VERSION 5.7 ;
  NOWIREEXTENSIONATPIN ON ;
  DIVIDERCHAR "/" ;
  BUSBITCHARS "[]" ;
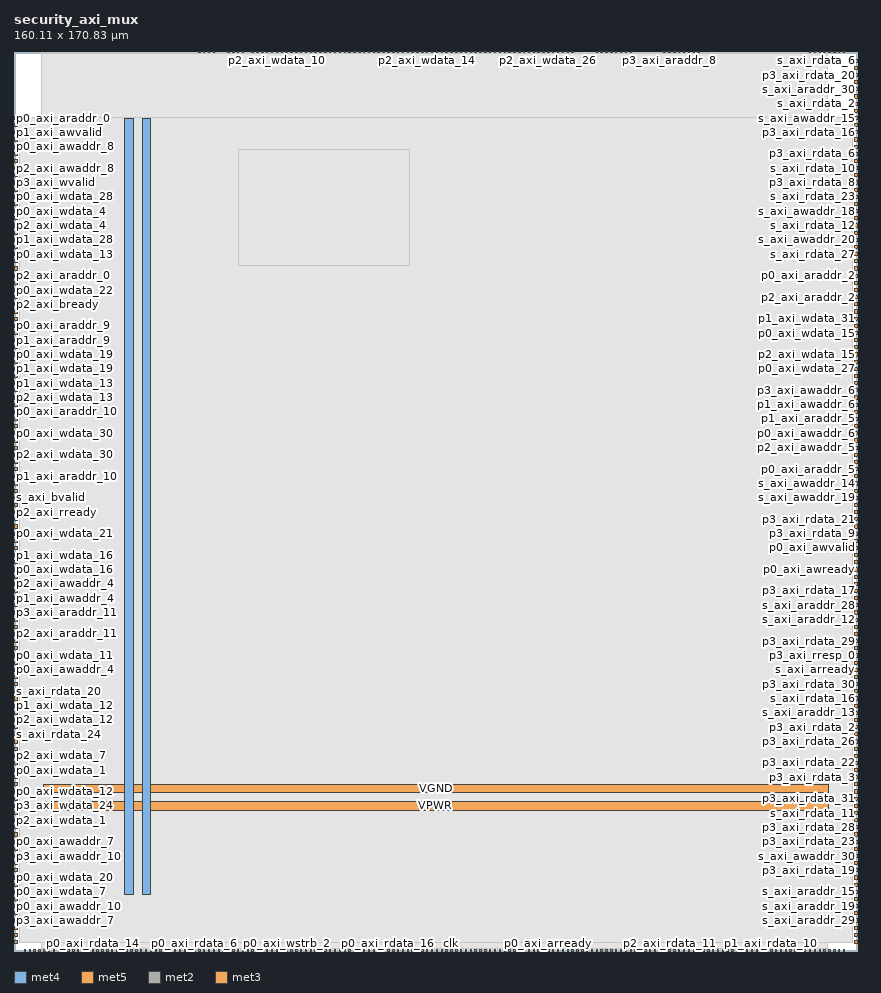
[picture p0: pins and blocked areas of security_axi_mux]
MACRO security_axi_mux
  CLASS BLOCK ;
  FOREIGN security_axi_mux ;
  ORIGIN 0.000 0.000 ;
  SIZE 160.110 BY 170.830 ;
  PIN VGND
    DIRECTION INOUT ;
    USE GROUND ;
    PORT
      LAYER met4 ;
        RECT 24.340 10.640 25.940 158.000 ;
    END
    PORT
      LAYER met5 ;
        RECT 5.520 30.030 154.560 31.630 ;
    END
  END VGND
  PIN VPWR
    DIRECTION INOUT ;
    USE POWER ;
    PORT
      LAYER met4 ;
        RECT 21.040 10.640 22.640 158.000 ;
    END
    PORT
      LAYER met5 ;
        RECT 5.520 26.730 154.560 28.330 ;
    END
  END VPWR
  PIN clk
    DIRECTION INPUT ;
    USE SIGNAL ;
    ANTENNAGATEAREA 1.286700 ;
    ANTENNADIFFAREA 0.434700 ;
    PORT
      LAYER met2 ;
        RECT 82.890 0.000 83.170 0.280 ;
    END
  END clk
  PIN p0_axi_araddr_0
    DIRECTION OUTPUT ;
    USE SIGNAL ;
    ANTENNAGATEAREA 0.434700 ;
    ANTENNADIFFAREA 1.137600 ;
    PORT
      LAYER met3 ;
        RECT 0.000 157.800 0.600 158.400 ;
    END
  END p0_axi_araddr_0
  PIN p0_axi_araddr_1
    DIRECTION OUTPUT ;
    USE SIGNAL ;
    ANTENNAGATEAREA 0.434700 ;
    ANTENNADIFFAREA 1.137600 ;
    PORT
      LAYER met2 ;
        RECT 50.690 0.000 50.970 0.280 ;
    END
  END p0_axi_araddr_1
  PIN p0_axi_araddr_10
    DIRECTION OUTPUT ;
    USE SIGNAL ;
    ANTENNAGATEAREA 0.434700 ;
    ANTENNADIFFAREA 1.137600 ;
    PORT
      LAYER met3 ;
        RECT 0.000 102.040 0.600 102.640 ;
    END
  END p0_axi_araddr_10
  PIN p0_axi_araddr_11
    DIRECTION OUTPUT ;
    USE SIGNAL ;
    ANTENNAGATEAREA 0.434700 ;
    ANTENNADIFFAREA 1.137600 ;
    PORT
      LAYER met3 ;
        RECT 0.000 1.400 0.600 2.000 ;
    END
  END p0_axi_araddr_11
  PIN p0_axi_araddr_2
    DIRECTION OUTPUT ;
    USE SIGNAL ;
    ANTENNAGATEAREA 0.434700 ;
    ANTENNADIFFAREA 1.137600 ;
    PORT
      LAYER met3 ;
        RECT 159.510 127.880 160.110 128.480 ;
    END
  END p0_axi_araddr_2
  PIN p0_axi_araddr_3
    DIRECTION OUTPUT ;
    USE SIGNAL ;
    ANTENNAGATEAREA 0.434700 ;
    ANTENNADIFFAREA 1.137600 ;
    PORT
      LAYER met2 ;
        RECT 68.170 170.550 68.450 170.830 ;
    END
  END p0_axi_araddr_3
  PIN p0_axi_araddr_4
    DIRECTION OUTPUT ;
    USE SIGNAL ;
    ANTENNAGATEAREA 0.434700 ;
    ANTENNADIFFAREA 1.137600 ;
    PORT
      LAYER met2 ;
        RECT 71.850 0.000 72.130 0.280 ;
    END
  END p0_axi_araddr_4
  PIN p0_axi_araddr_5
    DIRECTION OUTPUT ;
    USE SIGNAL ;
    ANTENNAGATEAREA 0.434700 ;
    ANTENNADIFFAREA 1.137600 ;
    PORT
      LAYER met3 ;
        RECT 159.510 91.160 160.110 91.760 ;
    END
  END p0_axi_araddr_5
  PIN p0_axi_araddr_6
    DIRECTION OUTPUT ;
    USE SIGNAL ;
    ANTENNAGATEAREA 0.434700 ;
    ANTENNADIFFAREA 1.137600 ;
    PORT
      LAYER met2 ;
        RECT 73.690 170.550 73.970 170.830 ;
    END
  END p0_axi_araddr_6
  PIN p0_axi_araddr_7
    DIRECTION OUTPUT ;
    USE SIGNAL ;
    ANTENNAGATEAREA 0.434700 ;
    ANTENNADIFFAREA 1.137600 ;
    PORT
      LAYER met2 ;
        RECT 98.530 170.550 98.810 170.830 ;
    END
  END p0_axi_araddr_7
  PIN p0_axi_araddr_8
    DIRECTION OUTPUT ;
    USE SIGNAL ;
    ANTENNAGATEAREA 0.434700 ;
    ANTENNADIFFAREA 1.137600 ;
    PORT
      LAYER met2 ;
        RECT 123.370 170.550 123.650 170.830 ;
    END
  END p0_axi_araddr_8
  PIN p0_axi_araddr_9
    DIRECTION OUTPUT ;
    USE SIGNAL ;
    ANTENNAGATEAREA 0.434700 ;
    ANTENNADIFFAREA 1.137600 ;
    PORT
      LAYER met3 ;
        RECT 0.000 118.360 0.600 118.960 ;
    END
  END p0_axi_araddr_9
  PIN p0_axi_arready
    DIRECTION INPUT ;
    USE SIGNAL ;
    ANTENNAGATEAREA 0.647700 ;
    ANTENNADIFFAREA 0.434700 ;
    PORT
      LAYER met2 ;
        RECT 101.290 0.000 101.570 0.280 ;
    END
  END p0_axi_arready
  PIN p0_axi_arvalid
    DIRECTION OUTPUT ;
    USE SIGNAL ;
    ANTENNAGATEAREA 0.434700 ;
    ANTENNADIFFAREA 1.137600 ;
    PORT
      LAYER met2 ;
        RECT 100.370 0.000 100.650 0.280 ;
    END
  END p0_axi_arvalid
  PIN p0_axi_awaddr_0
    DIRECTION OUTPUT ;
    USE SIGNAL ;
    ANTENNAGATEAREA 0.434700 ;
    ANTENNADIFFAREA 1.137600 ;
    PORT
      LAYER met2 ;
        RECT 127.050 170.550 127.330 170.830 ;
    END
  END p0_axi_awaddr_0
  PIN p0_axi_awaddr_1
    DIRECTION OUTPUT ;
    USE SIGNAL ;
    ANTENNAGATEAREA 0.434700 ;
    ANTENNADIFFAREA 1.137600 ;
    PORT
      LAYER met3 ;
        RECT 0.000 144.200 0.600 144.800 ;
    END
  END p0_axi_awaddr_1
  PIN p0_axi_awaddr_10
    DIRECTION OUTPUT ;
    USE SIGNAL ;
    ANTENNAGATEAREA 0.434700 ;
    ANTENNADIFFAREA 1.137600 ;
    PORT
      LAYER met3 ;
        RECT 0.000 8.200 0.600 8.800 ;
    END
  END p0_axi_awaddr_10
  PIN p0_axi_awaddr_11
    DIRECTION OUTPUT ;
    USE SIGNAL ;
    ANTENNAGATEAREA 0.434700 ;
    ANTENNADIFFAREA 1.137600 ;
    PORT
      LAYER met2 ;
        RECT 103.130 170.550 103.410 170.830 ;
    END
  END p0_axi_awaddr_11
  PIN p0_axi_awaddr_2
    DIRECTION OUTPUT ;
    USE SIGNAL ;
    ANTENNAGATEAREA 0.434700 ;
    ANTENNADIFFAREA 1.137600 ;
    PORT
      LAYER met2 ;
        RECT 44.250 0.000 44.530 0.280 ;
    END
  END p0_axi_awaddr_2
  PIN p0_axi_awaddr_3
    DIRECTION OUTPUT ;
    USE SIGNAL ;
    ANTENNAGATEAREA 0.434700 ;
    ANTENNADIFFAREA 1.137600 ;
    PORT
      LAYER met2 ;
        RECT 37.810 0.000 38.090 0.280 ;
    END
  END p0_axi_awaddr_3
  PIN p0_axi_awaddr_4
    DIRECTION OUTPUT ;
    USE SIGNAL ;
    ANTENNAGATEAREA 0.434700 ;
    ANTENNADIFFAREA 1.137600 ;
    PORT
      LAYER met3 ;
        RECT 0.000 53.080 0.600 53.680 ;
    END
  END p0_axi_awaddr_4
  PIN p0_axi_awaddr_5
    DIRECTION OUTPUT ;
    USE SIGNAL ;
    ANTENNAGATEAREA 0.434700 ;
    ANTENNADIFFAREA 1.137600 ;
    PORT
      LAYER met3 ;
        RECT 159.510 92.520 160.110 93.120 ;
    END
  END p0_axi_awaddr_5
  PIN p0_axi_awaddr_6
    DIRECTION OUTPUT ;
    USE SIGNAL ;
    ANTENNAGATEAREA 0.434700 ;
    ANTENNADIFFAREA 1.137600 ;
    PORT
      LAYER met3 ;
        RECT 159.510 97.960 160.110 98.560 ;
    END
  END p0_axi_awaddr_6
  PIN p0_axi_awaddr_7
    DIRECTION OUTPUT ;
    USE SIGNAL ;
    ANTENNAGATEAREA 0.434700 ;
    ANTENNADIFFAREA 1.137600 ;
    PORT
      LAYER met3 ;
        RECT 0.000 20.440 0.600 21.040 ;
    END
  END p0_axi_awaddr_7
  PIN p0_axi_awaddr_8
    DIRECTION OUTPUT ;
    USE SIGNAL ;
    ANTENNAGATEAREA 0.434700 ;
    ANTENNADIFFAREA 1.137600 ;
    PORT
      LAYER met3 ;
        RECT 0.000 152.360 0.600 152.960 ;
    END
  END p0_axi_awaddr_8
  PIN p0_axi_awaddr_9
    DIRECTION OUTPUT ;
    USE SIGNAL ;
    ANTENNAGATEAREA 0.434700 ;
    ANTENNADIFFAREA 1.137600 ;
    PORT
      LAYER met2 ;
        RECT 110.490 170.550 110.770 170.830 ;
    END
  END p0_axi_awaddr_9
  PIN p0_axi_awready
    DIRECTION INPUT ;
    USE SIGNAL ;
    ANTENNAGATEAREA 0.647700 ;
    ANTENNADIFFAREA 0.434700 ;
    PORT
      LAYER met3 ;
        RECT 159.510 72.120 160.110 72.720 ;
    END
  END p0_axi_awready
  PIN p0_axi_awvalid
    DIRECTION OUTPUT ;
    USE SIGNAL ;
    ANTENNAGATEAREA 0.434700 ;
    ANTENNADIFFAREA 1.137600 ;
    PORT
      LAYER met3 ;
        RECT 159.510 76.200 160.110 76.800 ;
    END
  END p0_axi_awvalid
  PIN p0_axi_bready
    DIRECTION OUTPUT ;
    USE SIGNAL ;
    ANTENNAGATEAREA 0.434700 ;
    ANTENNADIFFAREA 1.137600 ;
    PORT
      LAYER met3 ;
        RECT 0.000 126.520 0.600 127.120 ;
    END
  END p0_axi_bready
  PIN p0_axi_bresp_0
    DIRECTION INPUT ;
    USE SIGNAL ;
    PORT
      LAYER met2 ;
        RECT 2.850 0.000 3.130 0.280 ;
    END
  END p0_axi_bresp_0
  PIN p0_axi_bresp_1
    DIRECTION INPUT ;
    USE SIGNAL ;
    PORT
      LAYER met2 ;
        RECT 20.330 0.000 20.610 0.280 ;
    END
  END p0_axi_bresp_1
  PIN p0_axi_bvalid
    DIRECTION INPUT ;
    USE SIGNAL ;
    PORT
      LAYER met2 ;
        RECT 131.650 0.000 131.930 0.280 ;
    END
  END p0_axi_bvalid
  PIN p0_axi_rdata_0
    DIRECTION INPUT ;
    USE SIGNAL ;
    PORT
      LAYER met2 ;
        RECT 17.570 0.000 17.850 0.280 ;
    END
  END p0_axi_rdata_0
  PIN p0_axi_rdata_1
    DIRECTION INPUT ;
    USE SIGNAL ;
    PORT
      LAYER met2 ;
        RECT 152.810 0.000 153.090 0.280 ;
    END
  END p0_axi_rdata_1
  PIN p0_axi_rdata_10
    DIRECTION INPUT ;
    USE SIGNAL ;
    PORT
      LAYER met2 ;
        RECT 19.410 0.000 19.690 0.280 ;
    END
  END p0_axi_rdata_10
  PIN p0_axi_rdata_11
    DIRECTION INPUT ;
    USE SIGNAL ;
    PORT
      LAYER met2 ;
        RECT 149.130 0.000 149.410 0.280 ;
    END
  END p0_axi_rdata_11
  PIN p0_axi_rdata_12
    DIRECTION INPUT ;
    USE SIGNAL ;
    PORT
      LAYER met2 ;
        RECT 33.210 0.000 33.490 0.280 ;
    END
  END p0_axi_rdata_12
  PIN p0_axi_rdata_13
    DIRECTION INPUT ;
    USE SIGNAL ;
    PORT
      LAYER met2 ;
        RECT 27.690 0.000 27.970 0.280 ;
    END
  END p0_axi_rdata_13
  PIN p0_axi_rdata_14
    DIRECTION INPUT ;
    USE SIGNAL ;
    PORT
      LAYER met2 ;
        RECT 14.810 0.000 15.090 0.280 ;
    END
  END p0_axi_rdata_14
  PIN p0_axi_rdata_15
    DIRECTION INPUT ;
    USE SIGNAL ;
    PORT
      LAYER met2 ;
        RECT 154.650 0.000 154.930 0.280 ;
    END
  END p0_axi_rdata_15
  PIN p0_axi_rdata_16
    DIRECTION INPUT ;
    USE SIGNAL ;
    PORT
      LAYER met2 ;
        RECT 70.930 0.000 71.210 0.280 ;
    END
  END p0_axi_rdata_16
  PIN p0_axi_rdata_17
    DIRECTION INPUT ;
    USE SIGNAL ;
    PORT
      LAYER met2 ;
        RECT 30.450 0.000 30.730 0.280 ;
    END
  END p0_axi_rdata_17
  PIN p0_axi_rdata_18
    DIRECTION INPUT ;
    USE SIGNAL ;
    PORT
      LAYER met2 ;
        RECT 21.250 0.000 21.530 0.280 ;
    END
  END p0_axi_rdata_18
  PIN p0_axi_rdata_19
    DIRECTION INPUT ;
    USE SIGNAL ;
    PORT
      LAYER met2 ;
        RECT 18.490 0.000 18.770 0.280 ;
    END
  END p0_axi_rdata_19
  PIN p0_axi_rdata_2
    DIRECTION INPUT ;
    USE SIGNAL ;
    PORT
      LAYER met2 ;
        RECT 150.050 0.000 150.330 0.280 ;
    END
  END p0_axi_rdata_2
  PIN p0_axi_rdata_20
    DIRECTION INPUT ;
    USE SIGNAL ;
    PORT
      LAYER met2 ;
        RECT 146.370 0.000 146.650 0.280 ;
    END
  END p0_axi_rdata_20
  PIN p0_axi_rdata_21
    DIRECTION INPUT ;
    USE SIGNAL ;
    PORT
      LAYER met2 ;
        RECT 64.490 0.000 64.770 0.280 ;
    END
  END p0_axi_rdata_21
  PIN p0_axi_rdata_22
    DIRECTION INPUT ;
    USE SIGNAL ;
    PORT
      LAYER met2 ;
        RECT 25.850 0.000 26.130 0.280 ;
    END
  END p0_axi_rdata_22
  PIN p0_axi_rdata_23
    DIRECTION INPUT ;
    USE SIGNAL ;
    PORT
      LAYER met2 ;
        RECT 137.170 0.000 137.450 0.280 ;
    END
  END p0_axi_rdata_23
  PIN p0_axi_rdata_24
    DIRECTION INPUT ;
    USE SIGNAL ;
    PORT
      LAYER met2 ;
        RECT 32.290 0.000 32.570 0.280 ;
    END
  END p0_axi_rdata_24
  PIN p0_axi_rdata_25
    DIRECTION INPUT ;
    USE SIGNAL ;
    PORT
      LAYER met2 ;
        RECT 26.770 0.000 27.050 0.280 ;
    END
  END p0_axi_rdata_25
  PIN p0_axi_rdata_26
    DIRECTION INPUT ;
    USE SIGNAL ;
    PORT
      LAYER met2 ;
        RECT 155.570 0.000 155.850 0.280 ;
    END
  END p0_axi_rdata_26
  PIN p0_axi_rdata_27
    DIRECTION INPUT ;
    USE SIGNAL ;
    PORT
      LAYER met2 ;
        RECT 145.450 0.000 145.730 0.280 ;
    END
  END p0_axi_rdata_27
  PIN p0_axi_rdata_28
    DIRECTION INPUT ;
    USE SIGNAL ;
    PORT
      LAYER met2 ;
        RECT 69.090 0.000 69.370 0.280 ;
    END
  END p0_axi_rdata_28
  PIN p0_axi_rdata_29
    DIRECTION INPUT ;
    USE SIGNAL ;
    PORT
      LAYER met2 ;
        RECT 29.530 0.000 29.810 0.280 ;
    END
  END p0_axi_rdata_29
  PIN p0_axi_rdata_3
    DIRECTION INPUT ;
    USE SIGNAL ;
    PORT
      LAYER met2 ;
        RECT 31.370 0.000 31.650 0.280 ;
    END
  END p0_axi_rdata_3
  PIN p0_axi_rdata_30
    DIRECTION INPUT ;
    USE SIGNAL ;
    PORT
      LAYER met2 ;
        RECT 35.050 0.000 35.330 0.280 ;
    END
  END p0_axi_rdata_30
  PIN p0_axi_rdata_31
    DIRECTION INPUT ;
    USE SIGNAL ;
    PORT
      LAYER met2 ;
        RECT 47.930 0.000 48.210 0.280 ;
    END
  END p0_axi_rdata_31
  PIN p0_axi_rdata_4
    DIRECTION INPUT ;
    USE SIGNAL ;
    PORT
      LAYER met2 ;
        RECT 9.290 0.000 9.570 0.280 ;
    END
  END p0_axi_rdata_4
  PIN p0_axi_rdata_5
    DIRECTION INPUT ;
    USE SIGNAL ;
    PORT
      LAYER met2 ;
        RECT 81.050 0.000 81.330 0.280 ;
    END
  END p0_axi_rdata_5
  PIN p0_axi_rdata_6
    DIRECTION INPUT ;
    USE SIGNAL ;
    PORT
      LAYER met2 ;
        RECT 34.130 0.000 34.410 0.280 ;
    END
  END p0_axi_rdata_6
  PIN p0_axi_rdata_7
    DIRECTION INPUT ;
    USE SIGNAL ;
    PORT
      LAYER met2 ;
        RECT 87.490 0.000 87.770 0.280 ;
    END
  END p0_axi_rdata_7
  PIN p0_axi_rdata_8
    DIRECTION INPUT ;
    USE SIGNAL ;
    PORT
      LAYER met2 ;
        RECT 12.050 0.000 12.330 0.280 ;
    END
  END p0_axi_rdata_8
  PIN p0_axi_rdata_9
    DIRECTION INPUT ;
    USE SIGNAL ;
    PORT
      LAYER met2 ;
        RECT 86.570 0.000 86.850 0.280 ;
    END
  END p0_axi_rdata_9
  PIN p0_axi_rready
    DIRECTION OUTPUT ;
    USE SIGNAL ;
    ANTENNAGATEAREA 0.434700 ;
    ANTENNADIFFAREA 0.775300 ;
    PORT
      LAYER met2 ;
        RECT 66.330 0.000 66.610 0.280 ;
    END
  END p0_axi_rready
  PIN p0_axi_rresp_0
    DIRECTION INPUT ;
    USE SIGNAL ;
    PORT
      LAYER met2 ;
        RECT 16.650 0.000 16.930 0.280 ;
    END
  END p0_axi_rresp_0
  PIN p0_axi_rresp_1
    DIRECTION INPUT ;
    USE SIGNAL ;
    PORT
      LAYER met2 ;
        RECT 85.650 0.000 85.930 0.280 ;
    END
  END p0_axi_rresp_1
  PIN p0_axi_rvalid
    DIRECTION INPUT ;
    USE SIGNAL ;
    PORT
      LAYER met2 ;
        RECT 36.890 0.000 37.170 0.280 ;
    END
  END p0_axi_rvalid
  PIN p0_axi_wdata_0
    DIRECTION OUTPUT ;
    USE SIGNAL ;
    ANTENNAGATEAREA 0.434700 ;
    ANTENNADIFFAREA 1.137600 ;
    PORT
      LAYER met2 ;
        RECT 45.170 170.550 45.450 170.830 ;
    END
  END p0_axi_wdata_0
  PIN p0_axi_wdata_1
    DIRECTION OUTPUT ;
    USE SIGNAL ;
    ANTENNAGATEAREA 0.434700 ;
    ANTENNADIFFAREA 1.137600 ;
    PORT
      LAYER met3 ;
        RECT 0.000 34.040 0.600 34.640 ;
    END
  END p0_axi_wdata_1
  PIN p0_axi_wdata_10
    DIRECTION OUTPUT ;
    USE SIGNAL ;
    ANTENNAGATEAREA 0.434700 ;
    ANTENNADIFFAREA 1.137600 ;
    PORT
      LAYER met2 ;
        RECT 47.930 170.550 48.210 170.830 ;
    END
  END p0_axi_wdata_10
  PIN p0_axi_wdata_11
    DIRECTION OUTPUT ;
    USE SIGNAL ;
    ANTENNAGATEAREA 0.434700 ;
    ANTENNADIFFAREA 1.137600 ;
    PORT
      LAYER met3 ;
        RECT 0.000 55.800 0.600 56.400 ;
    END
  END p0_axi_wdata_11
  PIN p0_axi_wdata_12
    DIRECTION OUTPUT ;
    USE SIGNAL ;
    ANTENNAGATEAREA 0.434700 ;
    ANTENNADIFFAREA 1.137600 ;
    PORT
      LAYER met3 ;
        RECT 0.000 29.960 0.600 30.560 ;
    END
  END p0_axi_wdata_12
  PIN p0_axi_wdata_13
    DIRECTION OUTPUT ;
    USE SIGNAL ;
    ANTENNAGATEAREA 0.434700 ;
    ANTENNADIFFAREA 1.137600 ;
    PORT
      LAYER met3 ;
        RECT 0.000 131.960 0.600 132.560 ;
    END
  END p0_axi_wdata_13
  PIN p0_axi_wdata_14
    DIRECTION OUTPUT ;
    USE SIGNAL ;
    ANTENNAGATEAREA 0.434700 ;
    ANTENNADIFFAREA 1.137600 ;
    PORT
      LAYER met2 ;
        RECT 76.450 170.550 76.730 170.830 ;
    END
  END p0_axi_wdata_14
  PIN p0_axi_wdata_15
    DIRECTION OUTPUT ;
    USE SIGNAL ;
    ANTENNAGATEAREA 0.434700 ;
    ANTENNADIFFAREA 1.137600 ;
    PORT
      LAYER met3 ;
        RECT 159.510 117.000 160.110 117.600 ;
    END
  END p0_axi_wdata_15
  PIN p0_axi_wdata_16
    DIRECTION OUTPUT ;
    USE SIGNAL ;
    ANTENNAGATEAREA 0.434700 ;
    ANTENNADIFFAREA 1.137600 ;
    PORT
      LAYER met3 ;
        RECT 0.000 72.120 0.600 72.720 ;
    END
  END p0_axi_wdata_16
  PIN p0_axi_wdata_17
    DIRECTION OUTPUT ;
    USE SIGNAL ;
    ANTENNAGATEAREA 0.434700 ;
    ANTENNADIFFAREA 1.137600 ;
    PORT
      LAYER met2 ;
        RECT 35.050 170.550 35.330 170.830 ;
    END
  END p0_axi_wdata_17
  PIN p0_axi_wdata_18
    DIRECTION OUTPUT ;
    USE SIGNAL ;
    ANTENNAGATEAREA 0.434700 ;
    ANTENNADIFFAREA 1.137600 ;
    PORT
      LAYER met2 ;
        RECT 40.570 170.550 40.850 170.830 ;
    END
  END p0_axi_wdata_18
  PIN p0_axi_wdata_19
    DIRECTION OUTPUT ;
    USE SIGNAL ;
    ANTENNAGATEAREA 0.434700 ;
    ANTENNADIFFAREA 1.137600 ;
    PORT
      LAYER met3 ;
        RECT 0.000 112.920 0.600 113.520 ;
    END
  END p0_axi_wdata_19
  PIN p0_axi_wdata_2
    DIRECTION OUTPUT ;
    USE SIGNAL ;
    ANTENNAGATEAREA 0.434700 ;
    ANTENNADIFFAREA 1.137600 ;
    PORT
      LAYER met2 ;
        RECT 82.890 170.550 83.170 170.830 ;
    END
  END p0_axi_wdata_2
  PIN p0_axi_wdata_20
    DIRECTION OUTPUT ;
    USE SIGNAL ;
    ANTENNAGATEAREA 0.434700 ;
    ANTENNADIFFAREA 1.137600 ;
    PORT
      LAYER met3 ;
        RECT 0.000 13.640 0.600 14.240 ;
    END
  END p0_axi_wdata_20
  PIN p0_axi_wdata_21
    DIRECTION OUTPUT ;
    USE SIGNAL ;
    ANTENNAGATEAREA 0.434700 ;
    ANTENNADIFFAREA 1.137600 ;
    PORT
      LAYER met3 ;
        RECT 0.000 78.920 0.600 79.520 ;
    END
  END p0_axi_wdata_21
  PIN p0_axi_wdata_22
    DIRECTION OUTPUT ;
    USE SIGNAL ;
    ANTENNAGATEAREA 0.434700 ;
    ANTENNADIFFAREA 1.137600 ;
    PORT
      LAYER met3 ;
        RECT 0.000 125.160 0.600 125.760 ;
    END
  END p0_axi_wdata_22
  PIN p0_axi_wdata_23
    DIRECTION OUTPUT ;
    USE SIGNAL ;
    ANTENNAGATEAREA 0.434700 ;
    ANTENNADIFFAREA 1.137600 ;
    PORT
      LAYER met2 ;
        RECT 94.850 170.550 95.130 170.830 ;
    END
  END p0_axi_wdata_23
  PIN p0_axi_wdata_24
    DIRECTION OUTPUT ;
    USE SIGNAL ;
    ANTENNAGATEAREA 0.434700 ;
    ANTENNADIFFAREA 1.137600 ;
    PORT
      LAYER met2 ;
        RECT 65.410 0.000 65.690 0.280 ;
    END
  END p0_axi_wdata_24
  PIN p0_axi_wdata_25
    DIRECTION OUTPUT ;
    USE SIGNAL ;
    ANTENNAGATEAREA 0.434700 ;
    ANTENNADIFFAREA 1.137600 ;
    PORT
      LAYER met2 ;
        RECT 59.890 170.550 60.170 170.830 ;
    END
  END p0_axi_wdata_25
  PIN p0_axi_wdata_26
    DIRECTION OUTPUT ;
    USE SIGNAL ;
    ANTENNAGATEAREA 0.434700 ;
    ANTENNADIFFAREA 1.137600 ;
    PORT
      LAYER met2 ;
        RECT 99.450 170.550 99.730 170.830 ;
    END
  END p0_axi_wdata_26
  PIN p0_axi_wdata_27
    DIRECTION OUTPUT ;
    USE SIGNAL ;
    ANTENNAGATEAREA 0.434700 ;
    ANTENNADIFFAREA 1.137600 ;
    PORT
      LAYER met3 ;
        RECT 159.510 110.200 160.110 110.800 ;
    END
  END p0_axi_wdata_27
  PIN p0_axi_wdata_28
    DIRECTION OUTPUT ;
    USE SIGNAL ;
    ANTENNAGATEAREA 0.434700 ;
    ANTENNADIFFAREA 1.137600 ;
    PORT
      LAYER met3 ;
        RECT 0.000 142.840 0.600 143.440 ;
    END
  END p0_axi_wdata_28
  PIN p0_axi_wdata_29
    DIRECTION OUTPUT ;
    USE SIGNAL ;
    ANTENNAGATEAREA 0.434700 ;
    ANTENNADIFFAREA 1.137600 ;
    PORT
      LAYER met2 ;
        RECT 81.050 170.550 81.330 170.830 ;
    END
  END p0_axi_wdata_29
  PIN p0_axi_wdata_3
    DIRECTION OUTPUT ;
    USE SIGNAL ;
    ANTENNAGATEAREA 0.434700 ;
    ANTENNADIFFAREA 1.137600 ;
    PORT
      LAYER met2 ;
        RECT 60.810 170.550 61.090 170.830 ;
    END
  END p0_axi_wdata_3
  PIN p0_axi_wdata_30
    DIRECTION OUTPUT ;
    USE SIGNAL ;
    ANTENNAGATEAREA 0.434700 ;
    ANTENNADIFFAREA 1.137600 ;
    PORT
      LAYER met3 ;
        RECT 0.000 97.960 0.600 98.560 ;
    END
  END p0_axi_wdata_30
  PIN p0_axi_wdata_31
    DIRECTION OUTPUT ;
    USE SIGNAL ;
    ANTENNAGATEAREA 0.434700 ;
    ANTENNADIFFAREA 1.137600 ;
    PORT
      LAYER met3 ;
        RECT 159.510 118.360 160.110 118.960 ;
    END
  END p0_axi_wdata_31
  PIN p0_axi_wdata_4
    DIRECTION OUTPUT ;
    USE SIGNAL ;
    ANTENNAGATEAREA 0.434700 ;
    ANTENNADIFFAREA 1.137600 ;
    PORT
      LAYER met3 ;
        RECT 0.000 140.120 0.600 140.720 ;
    END
  END p0_axi_wdata_4
  PIN p0_axi_wdata_5
    DIRECTION OUTPUT ;
    USE SIGNAL ;
    ANTENNAGATEAREA 0.434700 ;
    ANTENNADIFFAREA 1.137600 ;
    PORT
      LAYER met2 ;
        RECT 39.650 0.000 39.930 0.280 ;
    END
  END p0_axi_wdata_5
  PIN p0_axi_wdata_6
    DIRECTION OUTPUT ;
    USE SIGNAL ;
    ANTENNAGATEAREA 0.434700 ;
    ANTENNADIFFAREA 1.137600 ;
    PORT
      LAYER met2 ;
        RECT 66.330 170.550 66.610 170.830 ;
    END
  END p0_axi_wdata_6
  PIN p0_axi_wdata_7
    DIRECTION OUTPUT ;
    USE SIGNAL ;
    ANTENNAGATEAREA 0.434700 ;
    ANTENNADIFFAREA 1.137600 ;
    PORT
      LAYER met3 ;
        RECT 0.000 10.920 0.600 11.520 ;
    END
  END p0_axi_wdata_7
  PIN p0_axi_wdata_8
    DIRECTION OUTPUT ;
    USE SIGNAL ;
    ANTENNAGATEAREA 0.434700 ;
    ANTENNADIFFAREA 1.137600 ;
    PORT
      LAYER met2 ;
        RECT 78.290 0.000 78.570 0.280 ;
    END
  END p0_axi_wdata_8
  PIN p0_axi_wdata_9
    DIRECTION OUTPUT ;
    USE SIGNAL ;
    ANTENNAGATEAREA 0.434700 ;
    ANTENNADIFFAREA 1.137600 ;
    PORT
      LAYER met2 ;
        RECT 47.010 170.550 47.290 170.830 ;
    END
  END p0_axi_wdata_9
  PIN p0_axi_wready
    DIRECTION INPUT ;
    USE SIGNAL ;
    PORT
      LAYER met2 ;
        RECT 7.450 0.000 7.730 0.280 ;
    END
  END p0_axi_wready
  PIN p0_axi_wstrb_0
    DIRECTION OUTPUT ;
    USE SIGNAL ;
    ANTENNAGATEAREA 0.434700 ;
    ANTENNADIFFAREA 1.137600 ;
    PORT
      LAYER met2 ;
        RECT 114.170 170.550 114.450 170.830 ;
    END
  END p0_axi_wstrb_0
  PIN p0_axi_wstrb_1
    DIRECTION OUTPUT ;
    USE SIGNAL ;
    ANTENNAGATEAREA 0.434700 ;
    ANTENNADIFFAREA 1.137600 ;
    PORT
      LAYER met3 ;
        RECT 0.000 133.320 0.600 133.920 ;
    END
  END p0_axi_wstrb_1
  PIN p0_axi_wstrb_2
    DIRECTION OUTPUT ;
    USE SIGNAL ;
    ANTENNAGATEAREA 0.434700 ;
    ANTENNADIFFAREA 1.137600 ;
    PORT
      LAYER met2 ;
        RECT 51.610 0.000 51.890 0.280 ;
    END
  END p0_axi_wstrb_2
  PIN p0_axi_wstrb_3
    DIRECTION OUTPUT ;
    USE SIGNAL ;
    ANTENNAGATEAREA 0.434700 ;
    ANTENNADIFFAREA 1.137600 ;
    PORT
      LAYER met2 ;
        RECT 88.410 170.550 88.690 170.830 ;
    END
  END p0_axi_wstrb_3
  PIN p0_axi_wvalid
    DIRECTION OUTPUT ;
    USE SIGNAL ;
    ANTENNAGATEAREA 0.434700 ;
    ANTENNADIFFAREA 0.775300 ;
    PORT
      LAYER met2 ;
        RECT 57.130 0.000 57.410 0.280 ;
    END
  END p0_axi_wvalid
  PIN p1_axi_araddr_0
    DIRECTION OUTPUT ;
    USE SIGNAL ;
    ANTENNAGATEAREA 0.434700 ;
    ANTENNADIFFAREA 1.137600 ;
    PORT
      LAYER met3 ;
        RECT 0.000 130.600 0.600 131.200 ;
    END
  END p1_axi_araddr_0
  PIN p1_axi_araddr_1
    DIRECTION OUTPUT ;
    USE SIGNAL ;
    ANTENNAGATEAREA 0.434700 ;
    ANTENNADIFFAREA 1.137600 ;
    PORT
      LAYER met2 ;
        RECT 54.370 0.000 54.650 0.280 ;
    END
  END p1_axi_araddr_1
  PIN p1_axi_araddr_10
    DIRECTION OUTPUT ;
    USE SIGNAL ;
    ANTENNAGATEAREA 0.434700 ;
    ANTENNADIFFAREA 1.137600 ;
    PORT
      LAYER met3 ;
        RECT 0.000 89.800 0.600 90.400 ;
    END
  END p1_axi_araddr_10
  PIN p1_axi_araddr_11
    DIRECTION OUTPUT ;
    USE SIGNAL ;
    ANTENNAGATEAREA 0.434700 ;
    ANTENNADIFFAREA 1.137600 ;
    PORT
      LAYER met3 ;
        RECT 0.000 61.240 0.600 61.840 ;
    END
  END p1_axi_araddr_11
  PIN p1_axi_araddr_2
    DIRECTION OUTPUT ;
    USE SIGNAL ;
    ANTENNAGATEAREA 0.434700 ;
    ANTENNADIFFAREA 1.137600 ;
    PORT
      LAYER met3 ;
        RECT 159.510 126.520 160.110 127.120 ;
    END
  END p1_axi_araddr_2
  PIN p1_axi_araddr_3
    DIRECTION OUTPUT ;
    USE SIGNAL ;
    ANTENNAGATEAREA 0.434700 ;
    ANTENNADIFFAREA 1.137600 ;
    PORT
      LAYER met2 ;
        RECT 67.250 170.550 67.530 170.830 ;
    END
  END p1_axi_araddr_3
  PIN p1_axi_araddr_4
    DIRECTION OUTPUT ;
    USE SIGNAL ;
    ANTENNAGATEAREA 0.434700 ;
    ANTENNADIFFAREA 1.137600 ;
    PORT
      LAYER met2 ;
        RECT 74.610 0.000 74.890 0.280 ;
    END
  END p1_axi_araddr_4
  PIN p1_axi_araddr_5
    DIRECTION OUTPUT ;
    USE SIGNAL ;
    ANTENNAGATEAREA 0.434700 ;
    ANTENNADIFFAREA 1.137600 ;
    PORT
      LAYER met3 ;
        RECT 159.510 100.680 160.110 101.280 ;
    END
  END p1_axi_araddr_5
  PIN p1_axi_araddr_6
    DIRECTION OUTPUT ;
    USE SIGNAL ;
    ANTENNAGATEAREA 0.434700 ;
    ANTENNADIFFAREA 1.137600 ;
    PORT
      LAYER met2 ;
        RECT 75.530 170.550 75.810 170.830 ;
    END
  END p1_axi_araddr_6
  PIN p1_axi_araddr_7
    DIRECTION OUTPUT ;
    USE SIGNAL ;
    ANTENNAGATEAREA 0.434700 ;
    ANTENNADIFFAREA 1.137600 ;
    PORT
      LAYER met2 ;
        RECT 93.010 170.550 93.290 170.830 ;
    END
  END p1_axi_araddr_7
  PIN p1_axi_araddr_8
    DIRECTION OUTPUT ;
    USE SIGNAL ;
    ANTENNAGATEAREA 0.434700 ;
    ANTENNADIFFAREA 1.137600 ;
    PORT
      LAYER met2 ;
        RECT 126.130 170.550 126.410 170.830 ;
    END
  END p1_axi_araddr_8
  PIN p1_axi_araddr_9
    DIRECTION OUTPUT ;
    USE SIGNAL ;
    ANTENNAGATEAREA 0.434700 ;
    ANTENNADIFFAREA 1.137600 ;
    PORT
      LAYER met3 ;
        RECT 0.000 115.640 0.600 116.240 ;
    END
  END p1_axi_araddr_9
  PIN p1_axi_arready
    DIRECTION INPUT ;
    USE SIGNAL ;
    PORT
      LAYER met2 ;
        RECT 13.890 0.000 14.170 0.280 ;
    END
  END p1_axi_arready
  PIN p1_axi_arvalid
    DIRECTION OUTPUT ;
    USE SIGNAL ;
    ANTENNAGATEAREA 0.434700 ;
    ANTENNADIFFAREA 0.775300 ;
    PORT
      LAYER met3 ;
        RECT 0.000 65.320 0.600 65.920 ;
    END
  END p1_axi_arvalid
  PIN p1_axi_awaddr_0
    DIRECTION OUTPUT ;
    USE SIGNAL ;
    ANTENNAGATEAREA 0.434700 ;
    ANTENNADIFFAREA 1.137600 ;
    PORT
      LAYER met2 ;
        RECT 128.890 170.550 129.170 170.830 ;
    END
  END p1_axi_awaddr_0
  PIN p1_axi_awaddr_1
    DIRECTION OUTPUT ;
    USE SIGNAL ;
    ANTENNAGATEAREA 0.434700 ;
    ANTENNADIFFAREA 1.137600 ;
    PORT
      LAYER met3 ;
        RECT 0.000 88.440 0.600 89.040 ;
    END
  END p1_axi_awaddr_1
  PIN p1_axi_awaddr_10
    DIRECTION OUTPUT ;
    USE SIGNAL ;
    ANTENNAGATEAREA 0.434700 ;
    ANTENNADIFFAREA 1.137600 ;
    PORT
      LAYER met3 ;
        RECT 0.000 19.080 0.600 19.680 ;
    END
  END p1_axi_awaddr_10
  PIN p1_axi_awaddr_11
    DIRECTION OUTPUT ;
    USE SIGNAL ;
    ANTENNAGATEAREA 0.434700 ;
    ANTENNADIFFAREA 1.137600 ;
    PORT
      LAYER met2 ;
        RECT 105.890 170.550 106.170 170.830 ;
    END
  END p1_axi_awaddr_11
  PIN p1_axi_awaddr_2
    DIRECTION OUTPUT ;
    USE SIGNAL ;
    ANTENNAGATEAREA 0.434700 ;
    ANTENNADIFFAREA 1.137600 ;
    PORT
      LAYER met2 ;
        RECT 47.010 0.000 47.290 0.280 ;
    END
  END p1_axi_awaddr_2
  PIN p1_axi_awaddr_3
    DIRECTION OUTPUT ;
    USE SIGNAL ;
    ANTENNAGATEAREA 0.434700 ;
    ANTENNADIFFAREA 1.137600 ;
    PORT
      LAYER met2 ;
        RECT 42.410 0.000 42.690 0.280 ;
    END
  END p1_axi_awaddr_3
  PIN p1_axi_awaddr_4
    DIRECTION OUTPUT ;
    USE SIGNAL ;
    ANTENNAGATEAREA 0.434700 ;
    ANTENNADIFFAREA 1.137600 ;
    PORT
      LAYER met3 ;
        RECT 0.000 66.680 0.600 67.280 ;
    END
  END p1_axi_awaddr_4
  PIN p1_axi_awaddr_5
    DIRECTION OUTPUT ;
    USE SIGNAL ;
    ANTENNAGATEAREA 0.434700 ;
    ANTENNADIFFAREA 1.137600 ;
    PORT
      LAYER met3 ;
        RECT 159.510 96.600 160.110 97.200 ;
    END
  END p1_axi_awaddr_5
  PIN p1_axi_awaddr_6
    DIRECTION OUTPUT ;
    USE SIGNAL ;
    ANTENNAGATEAREA 0.434700 ;
    ANTENNADIFFAREA 1.137600 ;
    PORT
      LAYER met3 ;
        RECT 159.510 103.400 160.110 104.000 ;
    END
  END p1_axi_awaddr_6
  PIN p1_axi_awaddr_7
    DIRECTION OUTPUT ;
    USE SIGNAL ;
    ANTENNAGATEAREA 0.434700 ;
    ANTENNADIFFAREA 1.137600 ;
    PORT
      LAYER met3 ;
        RECT 0.000 2.760 0.600 3.360 ;
    END
  END p1_axi_awaddr_7
  PIN p1_axi_awaddr_8
    DIRECTION OUTPUT ;
    USE SIGNAL ;
    ANTENNAGATEAREA 0.434700 ;
    ANTENNADIFFAREA 1.137600 ;
    PORT
      LAYER met3 ;
        RECT 0.000 151.000 0.600 151.600 ;
    END
  END p1_axi_awaddr_8
  PIN p1_axi_awaddr_9
    DIRECTION OUTPUT ;
    USE SIGNAL ;
    ANTENNAGATEAREA 0.434700 ;
    ANTENNADIFFAREA 1.137600 ;
    PORT
      LAYER met2 ;
        RECT 111.410 170.550 111.690 170.830 ;
    END
  END p1_axi_awaddr_9
  PIN p1_axi_awready
    DIRECTION INPUT ;
    USE SIGNAL ;
    PORT
      LAYER met2 ;
        RECT 12.970 0.000 13.250 0.280 ;
    END
  END p1_axi_awready
  PIN p1_axi_awvalid
    DIRECTION OUTPUT ;
    USE SIGNAL ;
    ANTENNAGATEAREA 0.434700 ;
    ANTENNADIFFAREA 0.775300 ;
    PORT
      LAYER met3 ;
        RECT 0.000 155.080 0.600 155.680 ;
    END
  END p1_axi_awvalid
  PIN p1_axi_bready
    DIRECTION OUTPUT ;
    USE SIGNAL ;
    ANTENNAGATEAREA 0.434700 ;
    ANTENNADIFFAREA 0.775300 ;
    PORT
      LAYER met3 ;
        RECT 0.000 146.920 0.600 147.520 ;
    END
  END p1_axi_bready
  PIN p1_axi_bresp_0
    DIRECTION INPUT ;
    USE SIGNAL ;
    PORT
      LAYER met2 ;
        RECT 15.730 0.000 16.010 0.280 ;
    END
  END p1_axi_bresp_0
  PIN p1_axi_bresp_1
    DIRECTION INPUT ;
    USE SIGNAL ;
    PORT
      LAYER met2 ;
        RECT 49.770 0.000 50.050 0.280 ;
    END
  END p1_axi_bresp_1
  PIN p1_axi_bvalid
    DIRECTION INPUT ;
    USE SIGNAL ;
    PORT
      LAYER met2 ;
        RECT 153.730 0.000 154.010 0.280 ;
    END
  END p1_axi_bvalid
  PIN p1_axi_rdata_0
    DIRECTION INPUT ;
    USE SIGNAL ;
    PORT
      LAYER met2 ;
        RECT 10.210 0.000 10.490 0.280 ;
    END
  END p1_axi_rdata_0
  PIN p1_axi_rdata_1
    DIRECTION INPUT ;
    USE SIGNAL ;
    PORT
      LAYER met2 ;
        RECT 24.010 0.000 24.290 0.280 ;
    END
  END p1_axi_rdata_1
  PIN p1_axi_rdata_10
    DIRECTION INPUT ;
    USE SIGNAL ;
    PORT
      LAYER met2 ;
        RECT 143.610 0.000 143.890 0.280 ;
    END
  END p1_axi_rdata_10
  PIN p1_axi_rdata_11
    DIRECTION INPUT ;
    USE SIGNAL ;
    PORT
      LAYER met2 ;
        RECT 4.690 0.000 4.970 0.280 ;
    END
  END p1_axi_rdata_11
  PIN p1_axi_rdata_12
    DIRECTION INPUT ;
    USE SIGNAL ;
    PORT
      LAYER met2 ;
        RECT 125.210 0.000 125.490 0.280 ;
    END
  END p1_axi_rdata_12
  PIN p1_axi_rdata_13
    DIRECTION INPUT ;
    USE SIGNAL ;
    PORT
      LAYER met2 ;
        RECT 11.130 0.000 11.410 0.280 ;
    END
  END p1_axi_rdata_13
  PIN p1_axi_rdata_14
    DIRECTION INPUT ;
    USE SIGNAL ;
    PORT
      LAYER met2 ;
        RECT 150.970 0.000 151.250 0.280 ;
    END
  END p1_axi_rdata_14
  PIN p1_axi_rdata_15
    DIRECTION INPUT ;
    USE SIGNAL ;
    PORT
      LAYER met2 ;
        RECT 48.850 0.000 49.130 0.280 ;
    END
  END p1_axi_rdata_15
  PIN p1_axi_rdata_16
    DIRECTION INPUT ;
    USE SIGNAL ;
    PORT
      LAYER met2 ;
        RECT 23.090 0.000 23.370 0.280 ;
    END
  END p1_axi_rdata_16
  PIN p1_axi_rdata_17
    DIRECTION INPUT ;
    USE SIGNAL ;
    PORT
      LAYER met2 ;
        RECT 1.930 0.000 2.210 0.280 ;
    END
  END p1_axi_rdata_17
  PIN p1_axi_rdata_18
    DIRECTION INPUT ;
    USE SIGNAL ;
    PORT
      LAYER met2 ;
        RECT 35.970 0.000 36.250 0.280 ;
    END
  END p1_axi_rdata_18
  PIN p1_axi_rdata_19
    DIRECTION INPUT ;
    USE SIGNAL ;
    PORT
      LAYER met2 ;
        RECT 128.890 0.000 129.170 0.280 ;
    END
  END p1_axi_rdata_19
  PIN p1_axi_rdata_2
    DIRECTION INPUT ;
    USE SIGNAL ;
    PORT
      LAYER met2 ;
        RECT 139.930 0.000 140.210 0.280 ;
    END
  END p1_axi_rdata_2
  PIN p1_axi_rdata_20
    DIRECTION INPUT ;
    USE SIGNAL ;
    PORT
      LAYER met2 ;
        RECT 8.370 0.000 8.650 0.280 ;
    END
  END p1_axi_rdata_20
  PIN p1_axi_rdata_21
    DIRECTION INPUT ;
    USE SIGNAL ;
    PORT
      LAYER met2 ;
        RECT 24.930 0.000 25.210 0.280 ;
    END
  END p1_axi_rdata_21
  PIN p1_axi_rdata_22
    DIRECTION INPUT ;
    USE SIGNAL ;
    PORT
      LAYER met2 ;
        RECT 147.290 0.000 147.570 0.280 ;
    END
  END p1_axi_rdata_22
  PIN p1_axi_rdata_23
    DIRECTION INPUT ;
    USE SIGNAL ;
    PORT
      LAYER met2 ;
        RECT 59.890 0.000 60.170 0.280 ;
    END
  END p1_axi_rdata_23
  PIN p1_axi_rdata_24
    DIRECTION INPUT ;
    USE SIGNAL ;
    PORT
      LAYER met2 ;
        RECT 140.850 0.000 141.130 0.280 ;
    END
  END p1_axi_rdata_24
  PIN p1_axi_rdata_25
    DIRECTION INPUT ;
    USE SIGNAL ;
    PORT
      LAYER met2 ;
        RECT 70.010 0.000 70.290 0.280 ;
    END
  END p1_axi_rdata_25
  PIN p1_axi_rdata_26
    DIRECTION INPUT ;
    USE SIGNAL ;
    PORT
      LAYER met2 ;
        RECT 138.090 0.000 138.370 0.280 ;
    END
  END p1_axi_rdata_26
  PIN p1_axi_rdata_27
    DIRECTION INPUT ;
    USE SIGNAL ;
    PORT
      LAYER met2 ;
        RECT 60.810 0.000 61.090 0.280 ;
    END
  END p1_axi_rdata_27
  PIN p1_axi_rdata_28
    DIRECTION INPUT ;
    USE SIGNAL ;
    PORT
      LAYER met2 ;
        RECT 61.730 0.000 62.010 0.280 ;
    END
  END p1_axi_rdata_28
  PIN p1_axi_rdata_29
    DIRECTION INPUT ;
    USE SIGNAL ;
    PORT
      LAYER met2 ;
        RECT 6.530 0.000 6.810 0.280 ;
    END
  END p1_axi_rdata_29
  PIN p1_axi_rdata_3
    DIRECTION INPUT ;
    USE SIGNAL ;
    PORT
      LAYER met2 ;
        RECT 63.570 0.000 63.850 0.280 ;
    END
  END p1_axi_rdata_3
  PIN p1_axi_rdata_30
    DIRECTION INPUT ;
    USE SIGNAL ;
    PORT
      LAYER met2 ;
        RECT 106.810 0.000 107.090 0.280 ;
    END
  END p1_axi_rdata_30
  PIN p1_axi_rdata_31
    DIRECTION INPUT ;
    USE SIGNAL ;
    PORT
      LAYER met2 ;
        RECT 108.650 0.000 108.930 0.280 ;
    END
  END p1_axi_rdata_31
  PIN p1_axi_rdata_4
    DIRECTION INPUT ;
    USE SIGNAL ;
    PORT
      LAYER met2 ;
        RECT 148.210 0.000 148.490 0.280 ;
    END
  END p1_axi_rdata_4
  PIN p1_axi_rdata_5
    DIRECTION INPUT ;
    USE SIGNAL ;
    PORT
      LAYER met2 ;
        RECT 90.250 0.000 90.530 0.280 ;
    END
  END p1_axi_rdata_5
  PIN p1_axi_rdata_6
    DIRECTION INPUT ;
    USE SIGNAL ;
    PORT
      LAYER met2 ;
        RECT 127.970 0.000 128.250 0.280 ;
    END
  END p1_axi_rdata_6
  PIN p1_axi_rdata_7
    DIRECTION INPUT ;
    USE SIGNAL ;
    PORT
      LAYER met2 ;
        RECT 109.570 0.000 109.850 0.280 ;
    END
  END p1_axi_rdata_7
  PIN p1_axi_rdata_8
    DIRECTION INPUT ;
    USE SIGNAL ;
    PORT
      LAYER met2 ;
        RECT 81.970 0.000 82.250 0.280 ;
    END
  END p1_axi_rdata_8
  PIN p1_axi_rdata_9
    DIRECTION INPUT ;
    USE SIGNAL ;
    PORT
      LAYER met2 ;
        RECT 28.610 0.000 28.890 0.280 ;
    END
  END p1_axi_rdata_9
  PIN p1_axi_rready
    DIRECTION OUTPUT ;
    USE SIGNAL ;
    ANTENNAGATEAREA 0.434700 ;
    ANTENNADIFFAREA 0.775300 ;
    PORT
      LAYER met2 ;
        RECT 58.050 0.000 58.330 0.280 ;
    END
  END p1_axi_rready
  PIN p1_axi_rresp_0
    DIRECTION INPUT ;
    USE SIGNAL ;
    PORT
      LAYER met2 ;
        RECT 97.610 0.000 97.890 0.280 ;
    END
  END p1_axi_rresp_0
  PIN p1_axi_rresp_1
    DIRECTION INPUT ;
    USE SIGNAL ;
    PORT
      LAYER met2 ;
        RECT 22.170 0.000 22.450 0.280 ;
    END
  END p1_axi_rresp_1
  PIN p1_axi_rvalid
    DIRECTION INPUT ;
    USE SIGNAL ;
    PORT
      LAYER met2 ;
        RECT 76.450 0.000 76.730 0.280 ;
    END
  END p1_axi_rvalid
  PIN p1_axi_wdata_0
    DIRECTION OUTPUT ;
    USE SIGNAL ;
    ANTENNAGATEAREA 0.434700 ;
    ANTENNADIFFAREA 1.137600 ;
    PORT
      LAYER met2 ;
        RECT 58.050 170.550 58.330 170.830 ;
    END
  END p1_axi_wdata_0
  PIN p1_axi_wdata_1
    DIRECTION OUTPUT ;
    USE SIGNAL ;
    ANTENNAGATEAREA 0.434700 ;
    ANTENNADIFFAREA 1.137600 ;
    PORT
      LAYER met3 ;
        RECT 0.000 15.000 0.600 15.600 ;
    END
  END p1_axi_wdata_1
  PIN p1_axi_wdata_10
    DIRECTION OUTPUT ;
    USE SIGNAL ;
    ANTENNAGATEAREA 0.434700 ;
    ANTENNADIFFAREA 1.137600 ;
    PORT
      LAYER met2 ;
        RECT 50.690 170.550 50.970 170.830 ;
    END
  END p1_axi_wdata_10
  PIN p1_axi_wdata_11
    DIRECTION OUTPUT ;
    USE SIGNAL ;
    ANTENNAGATEAREA 0.434700 ;
    ANTENNADIFFAREA 1.137600 ;
    PORT
      LAYER met3 ;
        RECT 0.000 51.720 0.600 52.320 ;
    END
  END p1_axi_wdata_11
  PIN p1_axi_wdata_12
    DIRECTION OUTPUT ;
    USE SIGNAL ;
    ANTENNAGATEAREA 0.434700 ;
    ANTENNADIFFAREA 1.137600 ;
    PORT
      LAYER met3 ;
        RECT 0.000 46.280 0.600 46.880 ;
    END
  END p1_axi_wdata_12
  PIN p1_axi_wdata_13
    DIRECTION OUTPUT ;
    USE SIGNAL ;
    ANTENNAGATEAREA 0.434700 ;
    ANTENNADIFFAREA 1.137600 ;
    PORT
      LAYER met3 ;
        RECT 0.000 107.480 0.600 108.080 ;
    END
  END p1_axi_wdata_13
  PIN p1_axi_wdata_14
    DIRECTION OUTPUT ;
    USE SIGNAL ;
    ANTENNAGATEAREA 0.434700 ;
    ANTENNADIFFAREA 1.137600 ;
    PORT
      LAYER met2 ;
        RECT 77.370 170.550 77.650 170.830 ;
    END
  END p1_axi_wdata_14
  PIN p1_axi_wdata_15
    DIRECTION OUTPUT ;
    USE SIGNAL ;
    ANTENNAGATEAREA 0.434700 ;
    ANTENNADIFFAREA 1.137600 ;
    PORT
      LAYER met3 ;
        RECT 159.510 115.640 160.110 116.240 ;
    END
  END p1_axi_wdata_15
  PIN p1_axi_wdata_16
    DIRECTION OUTPUT ;
    USE SIGNAL ;
    ANTENNAGATEAREA 0.434700 ;
    ANTENNADIFFAREA 1.137600 ;
    PORT
      LAYER met3 ;
        RECT 0.000 74.840 0.600 75.440 ;
    END
  END p1_axi_wdata_16
  PIN p1_axi_wdata_17
    DIRECTION OUTPUT ;
    USE SIGNAL ;
    ANTENNAGATEAREA 0.434700 ;
    ANTENNADIFFAREA 1.137600 ;
    PORT
      LAYER met2 ;
        RECT 35.970 170.550 36.250 170.830 ;
    END
  END p1_axi_wdata_17
  PIN p1_axi_wdata_18
    DIRECTION OUTPUT ;
    USE SIGNAL ;
    ANTENNAGATEAREA 0.434700 ;
    ANTENNADIFFAREA 1.137600 ;
    PORT
      LAYER met2 ;
        RECT 42.410 170.550 42.690 170.830 ;
    END
  END p1_axi_wdata_18
  PIN p1_axi_wdata_19
    DIRECTION OUTPUT ;
    USE SIGNAL ;
    ANTENNAGATEAREA 0.434700 ;
    ANTENNADIFFAREA 1.137600 ;
    PORT
      LAYER met3 ;
        RECT 0.000 110.200 0.600 110.800 ;
    END
  END p1_axi_wdata_19
  PIN p1_axi_wdata_2
    DIRECTION OUTPUT ;
    USE SIGNAL ;
    ANTENNAGATEAREA 0.434700 ;
    ANTENNADIFFAREA 1.137600 ;
    PORT
      LAYER met2 ;
        RECT 85.650 170.550 85.930 170.830 ;
    END
  END p1_axi_wdata_2
  PIN p1_axi_wdata_20
    DIRECTION OUTPUT ;
    USE SIGNAL ;
    ANTENNAGATEAREA 0.434700 ;
    ANTENNADIFFAREA 1.137600 ;
    PORT
      LAYER met3 ;
        RECT 0.000 47.640 0.600 48.240 ;
    END
  END p1_axi_wdata_20
  PIN p1_axi_wdata_21
    DIRECTION OUTPUT ;
    USE SIGNAL ;
    ANTENNAGATEAREA 0.434700 ;
    ANTENNADIFFAREA 1.137600 ;
    PORT
      LAYER met3 ;
        RECT 0.000 156.440 0.600 157.040 ;
    END
  END p1_axi_wdata_21
  PIN p1_axi_wdata_22
    DIRECTION OUTPUT ;
    USE SIGNAL ;
    ANTENNAGATEAREA 0.434700 ;
    ANTENNADIFFAREA 1.137600 ;
    PORT
      LAYER met3 ;
        RECT 0.000 123.800 0.600 124.400 ;
    END
  END p1_axi_wdata_22
  PIN p1_axi_wdata_23
    DIRECTION OUTPUT ;
    USE SIGNAL ;
    ANTENNAGATEAREA 0.434700 ;
    ANTENNADIFFAREA 1.137600 ;
    PORT
      LAYER met2 ;
        RECT 97.610 170.550 97.890 170.830 ;
    END
  END p1_axi_wdata_23
  PIN p1_axi_wdata_24
    DIRECTION OUTPUT ;
    USE SIGNAL ;
    ANTENNAGATEAREA 0.434700 ;
    ANTENNADIFFAREA 1.137600 ;
    PORT
      LAYER met2 ;
        RECT 68.170 0.000 68.450 0.280 ;
    END
  END p1_axi_wdata_24
  PIN p1_axi_wdata_25
    DIRECTION OUTPUT ;
    USE SIGNAL ;
    ANTENNAGATEAREA 0.434700 ;
    ANTENNADIFFAREA 1.137600 ;
    PORT
      LAYER met2 ;
        RECT 56.210 170.550 56.490 170.830 ;
    END
  END p1_axi_wdata_25
  PIN p1_axi_wdata_26
    DIRECTION OUTPUT ;
    USE SIGNAL ;
    ANTENNAGATEAREA 0.434700 ;
    ANTENNADIFFAREA 1.137600 ;
    PORT
      LAYER met2 ;
        RECT 102.210 170.550 102.490 170.830 ;
    END
  END p1_axi_wdata_26
  PIN p1_axi_wdata_27
    DIRECTION OUTPUT ;
    USE SIGNAL ;
    ANTENNAGATEAREA 0.434700 ;
    ANTENNADIFFAREA 1.137600 ;
    PORT
      LAYER met3 ;
        RECT 159.510 111.560 160.110 112.160 ;
    END
  END p1_axi_wdata_27
  PIN p1_axi_wdata_28
    DIRECTION OUTPUT ;
    USE SIGNAL ;
    ANTENNAGATEAREA 0.434700 ;
    ANTENNADIFFAREA 1.137600 ;
    PORT
      LAYER met3 ;
        RECT 0.000 134.680 0.600 135.280 ;
    END
  END p1_axi_wdata_28
  PIN p1_axi_wdata_29
    DIRECTION OUTPUT ;
    USE SIGNAL ;
    ANTENNAGATEAREA 0.434700 ;
    ANTENNADIFFAREA 1.137600 ;
    PORT
      LAYER met2 ;
        RECT 81.970 170.550 82.250 170.830 ;
    END
  END p1_axi_wdata_29
  PIN p1_axi_wdata_3
    DIRECTION OUTPUT ;
    USE SIGNAL ;
    ANTENNAGATEAREA 0.434700 ;
    ANTENNADIFFAREA 1.137600 ;
    PORT
      LAYER met2 ;
        RECT 61.730 170.550 62.010 170.830 ;
    END
  END p1_axi_wdata_3
  PIN p1_axi_wdata_30
    DIRECTION OUTPUT ;
    USE SIGNAL ;
    ANTENNAGATEAREA 0.434700 ;
    ANTENNADIFFAREA 1.137600 ;
    PORT
      LAYER met3 ;
        RECT 0.000 96.600 0.600 97.200 ;
    END
  END p1_axi_wdata_30
  PIN p1_axi_wdata_31
    DIRECTION OUTPUT ;
    USE SIGNAL ;
    ANTENNAGATEAREA 0.434700 ;
    ANTENNADIFFAREA 1.137600 ;
    PORT
      LAYER met3 ;
        RECT 159.510 119.720 160.110 120.320 ;
    END
  END p1_axi_wdata_31
  PIN p1_axi_wdata_4
    DIRECTION OUTPUT ;
    USE SIGNAL ;
    ANTENNAGATEAREA 0.434700 ;
    ANTENNADIFFAREA 1.137600 ;
    PORT
      LAYER met3 ;
        RECT 0.000 138.760 0.600 139.360 ;
    END
  END p1_axi_wdata_4
  PIN p1_axi_wdata_5
    DIRECTION OUTPUT ;
    USE SIGNAL ;
    ANTENNAGATEAREA 0.434700 ;
    ANTENNADIFFAREA 1.137600 ;
    PORT
      LAYER met2 ;
        RECT 40.570 0.000 40.850 0.280 ;
    END
  END p1_axi_wdata_5
  PIN p1_axi_wdata_6
    DIRECTION OUTPUT ;
    USE SIGNAL ;
    ANTENNAGATEAREA 0.434700 ;
    ANTENNADIFFAREA 1.137600 ;
    PORT
      LAYER met2 ;
        RECT 71.850 170.550 72.130 170.830 ;
    END
  END p1_axi_wdata_6
  PIN p1_axi_wdata_7
    DIRECTION OUTPUT ;
    USE SIGNAL ;
    ANTENNAGATEAREA 0.434700 ;
    ANTENNADIFFAREA 1.137600 ;
    PORT
      LAYER met3 ;
        RECT 0.000 54.440 0.600 55.040 ;
    END
  END p1_axi_wdata_7
  PIN p1_axi_wdata_8
    DIRECTION OUTPUT ;
    USE SIGNAL ;
    ANTENNAGATEAREA 0.434700 ;
    ANTENNADIFFAREA 1.137600 ;
    PORT
      LAYER met2 ;
        RECT 80.130 0.000 80.410 0.280 ;
    END
  END p1_axi_wdata_8
  PIN p1_axi_wdata_9
    DIRECTION OUTPUT ;
    USE SIGNAL ;
    ANTENNAGATEAREA 0.434700 ;
    ANTENNADIFFAREA 1.137600 ;
    PORT
      LAYER met2 ;
        RECT 54.370 170.550 54.650 170.830 ;
    END
  END p1_axi_wdata_9
  PIN p1_axi_wready
    DIRECTION INPUT ;
    USE SIGNAL ;
    PORT
      LAYER met2 ;
        RECT 98.530 0.000 98.810 0.280 ;
    END
  END p1_axi_wready
  PIN p1_axi_wstrb_0
    DIRECTION OUTPUT ;
    USE SIGNAL ;
    ANTENNAGATEAREA 0.434700 ;
    ANTENNADIFFAREA 1.137600 ;
    PORT
      LAYER met2 ;
        RECT 115.090 170.550 115.370 170.830 ;
    END
  END p1_axi_wstrb_0
  PIN p1_axi_wstrb_1
    DIRECTION OUTPUT ;
    USE SIGNAL ;
    ANTENNAGATEAREA 0.434700 ;
    ANTENNADIFFAREA 1.137600 ;
    PORT
      LAYER met2 ;
        RECT 63.570 170.550 63.850 170.830 ;
    END
  END p1_axi_wstrb_1
  PIN p1_axi_wstrb_2
    DIRECTION OUTPUT ;
    USE SIGNAL ;
    ANTENNAGATEAREA 0.434700 ;
    ANTENNADIFFAREA 1.137600 ;
    PORT
      LAYER met2 ;
        RECT 55.290 0.000 55.570 0.280 ;
    END
  END p1_axi_wstrb_2
  PIN p1_axi_wstrb_3
    DIRECTION OUTPUT ;
    USE SIGNAL ;
    ANTENNAGATEAREA 0.434700 ;
    ANTENNADIFFAREA 1.137600 ;
    PORT
      LAYER met2 ;
        RECT 89.330 170.550 89.610 170.830 ;
    END
  END p1_axi_wstrb_3
  PIN p1_axi_wvalid
    DIRECTION OUTPUT ;
    USE SIGNAL ;
    ANTENNAGATEAREA 0.434700 ;
    ANTENNADIFFAREA 0.775300 ;
    PORT
      LAYER met2 ;
        RECT 62.650 0.000 62.930 0.280 ;
    END
  END p1_axi_wvalid
  PIN p2_axi_araddr_0
    DIRECTION OUTPUT ;
    USE SIGNAL ;
    ANTENNAGATEAREA 0.434700 ;
    ANTENNADIFFAREA 1.137600 ;
    PORT
      LAYER met3 ;
        RECT 0.000 127.880 0.600 128.480 ;
    END
  END p2_axi_araddr_0
  PIN p2_axi_araddr_1
    DIRECTION OUTPUT ;
    USE SIGNAL ;
    ANTENNAGATEAREA 0.434700 ;
    ANTENNADIFFAREA 1.137600 ;
    PORT
      LAYER met2 ;
        RECT 52.530 0.000 52.810 0.280 ;
    END
  END p2_axi_araddr_1
  PIN p2_axi_araddr_10
    DIRECTION OUTPUT ;
    USE SIGNAL ;
    ANTENNAGATEAREA 0.434700 ;
    ANTENNADIFFAREA 1.137600 ;
    PORT
      LAYER met3 ;
        RECT 0.000 91.160 0.600 91.760 ;
    END
  END p2_axi_araddr_10
  PIN p2_axi_araddr_11
    DIRECTION OUTPUT ;
    USE SIGNAL ;
    ANTENNAGATEAREA 0.434700 ;
    ANTENNADIFFAREA 1.137600 ;
    PORT
      LAYER met3 ;
        RECT 0.000 59.880 0.600 60.480 ;
    END
  END p2_axi_araddr_11
  PIN p2_axi_araddr_2
    DIRECTION OUTPUT ;
    USE SIGNAL ;
    ANTENNAGATEAREA 0.434700 ;
    ANTENNADIFFAREA 1.137600 ;
    PORT
      LAYER met3 ;
        RECT 159.510 123.800 160.110 124.400 ;
    END
  END p2_axi_araddr_2
  PIN p2_axi_araddr_3
    DIRECTION OUTPUT ;
    USE SIGNAL ;
    ANTENNAGATEAREA 0.434700 ;
    ANTENNADIFFAREA 1.137600 ;
    PORT
      LAYER met2 ;
        RECT 69.090 170.550 69.370 170.830 ;
    END
  END p2_axi_araddr_3
  PIN p2_axi_araddr_4
    DIRECTION OUTPUT ;
    USE SIGNAL ;
    ANTENNAGATEAREA 0.434700 ;
    ANTENNADIFFAREA 1.137600 ;
    PORT
      LAYER met2 ;
        RECT 73.690 0.000 73.970 0.280 ;
    END
  END p2_axi_araddr_4
  PIN p2_axi_araddr_5
    DIRECTION OUTPUT ;
    USE SIGNAL ;
    ANTENNAGATEAREA 0.434700 ;
    ANTENNADIFFAREA 1.137600 ;
    PORT
      LAYER met3 ;
        RECT 159.510 102.040 160.110 102.640 ;
    END
  END p2_axi_araddr_5
  PIN p2_axi_araddr_6
    DIRECTION OUTPUT ;
    USE SIGNAL ;
    ANTENNAGATEAREA 0.434700 ;
    ANTENNADIFFAREA 1.137600 ;
    PORT
      LAYER met2 ;
        RECT 80.130 170.550 80.410 170.830 ;
    END
  END p2_axi_araddr_6
  PIN p2_axi_araddr_7
    DIRECTION OUTPUT ;
    USE SIGNAL ;
    ANTENNAGATEAREA 0.434700 ;
    ANTENNADIFFAREA 1.137600 ;
    PORT
      LAYER met2 ;
        RECT 91.170 170.550 91.450 170.830 ;
    END
  END p2_axi_araddr_7
  PIN p2_axi_araddr_8
    DIRECTION OUTPUT ;
    USE SIGNAL ;
    ANTENNAGATEAREA 0.434700 ;
    ANTENNADIFFAREA 1.137600 ;
    PORT
      LAYER met2 ;
        RECT 125.210 170.550 125.490 170.830 ;
    END
  END p2_axi_araddr_8
  PIN p2_axi_araddr_9
    DIRECTION OUTPUT ;
    USE SIGNAL ;
    ANTENNAGATEAREA 0.434700 ;
    ANTENNADIFFAREA 1.137600 ;
    PORT
      LAYER met3 ;
        RECT 0.000 117.000 0.600 117.600 ;
    END
  END p2_axi_araddr_9
  PIN p2_axi_arready
    DIRECTION INPUT ;
    USE SIGNAL ;
    PORT
      LAYER met2 ;
        RECT 75.530 0.000 75.810 0.280 ;
    END
  END p2_axi_arready
  PIN p2_axi_arvalid
    DIRECTION OUTPUT ;
    USE SIGNAL ;
    ANTENNAGATEAREA 0.434700 ;
    ANTENNADIFFAREA 1.137600 ;
    PORT
      LAYER met2 ;
        RECT 103.130 0.000 103.410 0.280 ;
    END
  END p2_axi_arvalid
  PIN p2_axi_awaddr_0
    DIRECTION OUTPUT ;
    USE SIGNAL ;
    ANTENNAGATEAREA 0.434700 ;
    ANTENNADIFFAREA 1.137600 ;
    PORT
      LAYER met2 ;
        RECT 129.810 170.550 130.090 170.830 ;
    END
  END p2_axi_awaddr_0
  PIN p2_axi_awaddr_1
    DIRECTION OUTPUT ;
    USE SIGNAL ;
    ANTENNAGATEAREA 0.434700 ;
    ANTENNADIFFAREA 1.137600 ;
    PORT
      LAYER met3 ;
        RECT 0.000 99.320 0.600 99.920 ;
    END
  END p2_axi_awaddr_1
  PIN p2_axi_awaddr_10
    DIRECTION OUTPUT ;
    USE SIGNAL ;
    ANTENNAGATEAREA 0.434700 ;
    ANTENNADIFFAREA 1.137600 ;
    PORT
      LAYER met3 ;
        RECT 0.000 6.840 0.600 7.440 ;
    END
  END p2_axi_awaddr_10
  PIN p2_axi_awaddr_11
    DIRECTION OUTPUT ;
    USE SIGNAL ;
    ANTENNAGATEAREA 0.434700 ;
    ANTENNADIFFAREA 1.137600 ;
    PORT
      LAYER met2 ;
        RECT 104.970 170.550 105.250 170.830 ;
    END
  END p2_axi_awaddr_11
  PIN p2_axi_awaddr_2
    DIRECTION OUTPUT ;
    USE SIGNAL ;
    ANTENNAGATEAREA 0.434700 ;
    ANTENNADIFFAREA 1.137600 ;
    PORT
      LAYER met2 ;
        RECT 46.090 0.000 46.370 0.280 ;
    END
  END p2_axi_awaddr_2
  PIN p2_axi_awaddr_3
    DIRECTION OUTPUT ;
    USE SIGNAL ;
    ANTENNAGATEAREA 0.434700 ;
    ANTENNADIFFAREA 1.137600 ;
    PORT
      LAYER met2 ;
        RECT 43.330 0.000 43.610 0.280 ;
    END
  END p2_axi_awaddr_3
  PIN p2_axi_awaddr_4
    DIRECTION OUTPUT ;
    USE SIGNAL ;
    ANTENNAGATEAREA 0.434700 ;
    ANTENNADIFFAREA 1.137600 ;
    PORT
      LAYER met3 ;
        RECT 0.000 69.400 0.600 70.000 ;
    END
  END p2_axi_awaddr_4
  PIN p2_axi_awaddr_5
    DIRECTION OUTPUT ;
    USE SIGNAL ;
    ANTENNAGATEAREA 0.434700 ;
    ANTENNADIFFAREA 1.137600 ;
    PORT
      LAYER met3 ;
        RECT 159.510 95.240 160.110 95.840 ;
    END
  END p2_axi_awaddr_5
  PIN p2_axi_awaddr_6
    DIRECTION OUTPUT ;
    USE SIGNAL ;
    ANTENNAGATEAREA 0.434700 ;
    ANTENNADIFFAREA 1.137600 ;
    PORT
      LAYER met3 ;
        RECT 159.510 104.760 160.110 105.360 ;
    END
  END p2_axi_awaddr_6
  PIN p2_axi_awaddr_7
    DIRECTION OUTPUT ;
    USE SIGNAL ;
    ANTENNAGATEAREA 0.434700 ;
    ANTENNADIFFAREA 1.137600 ;
    PORT
      LAYER met3 ;
        RECT 0.000 9.560 0.600 10.160 ;
    END
  END p2_axi_awaddr_7
  PIN p2_axi_awaddr_8
    DIRECTION OUTPUT ;
    USE SIGNAL ;
    ANTENNAGATEAREA 0.434700 ;
    ANTENNADIFFAREA 1.137600 ;
    PORT
      LAYER met3 ;
        RECT 0.000 148.280 0.600 148.880 ;
    END
  END p2_axi_awaddr_8
  PIN p2_axi_awaddr_9
    DIRECTION OUTPUT ;
    USE SIGNAL ;
    ANTENNAGATEAREA 0.434700 ;
    ANTENNADIFFAREA 1.137600 ;
    PORT
      LAYER met2 ;
        RECT 112.330 170.550 112.610 170.830 ;
    END
  END p2_axi_awaddr_9
  PIN p2_axi_awready
    DIRECTION INPUT ;
    USE SIGNAL ;
    PORT
      LAYER met2 ;
        RECT 129.810 0.000 130.090 0.280 ;
    END
  END p2_axi_awready
  PIN p2_axi_awvalid
    DIRECTION OUTPUT ;
    USE SIGNAL ;
    ANTENNAGATEAREA 0.434700 ;
    ANTENNADIFFAREA 1.137600 ;
    PORT
      LAYER met3 ;
        RECT 159.510 74.840 160.110 75.440 ;
    END
  END p2_axi_awvalid
  PIN p2_axi_bready
    DIRECTION OUTPUT ;
    USE SIGNAL ;
    ANTENNAGATEAREA 0.434700 ;
    ANTENNADIFFAREA 1.137600 ;
    PORT
      LAYER met3 ;
        RECT 0.000 122.440 0.600 123.040 ;
    END
  END p2_axi_bready
  PIN p2_axi_bresp_0
    DIRECTION INPUT ;
    USE SIGNAL ;
    PORT
      LAYER met2 ;
        RECT 77.370 0.000 77.650 0.280 ;
    END
  END p2_axi_bresp_0
  PIN p2_axi_bresp_1
    DIRECTION INPUT ;
    USE SIGNAL ;
    PORT
      LAYER met2 ;
        RECT 99.450 0.000 99.730 0.280 ;
    END
  END p2_axi_bresp_1
  PIN p2_axi_bvalid
    DIRECTION INPUT ;
    USE SIGNAL ;
    PORT
      LAYER met2 ;
        RECT 93.930 0.000 94.210 0.280 ;
    END
  END p2_axi_bvalid
  PIN p2_axi_rdata_0
    DIRECTION INPUT ;
    USE SIGNAL ;
    PORT
      LAYER met2 ;
        RECT 83.810 0.000 84.090 0.280 ;
    END
  END p2_axi_rdata_0
  PIN p2_axi_rdata_1
    DIRECTION INPUT ;
    USE SIGNAL ;
    PORT
      LAYER met2 ;
        RECT 134.410 0.000 134.690 0.280 ;
    END
  END p2_axi_rdata_1
  PIN p2_axi_rdata_10
    DIRECTION INPUT ;
    USE SIGNAL ;
    PORT
      LAYER met2 ;
        RECT 130.730 0.000 131.010 0.280 ;
    END
  END p2_axi_rdata_10
  PIN p2_axi_rdata_11
    DIRECTION INPUT ;
    USE SIGNAL ;
    PORT
      LAYER met2 ;
        RECT 124.290 0.000 124.570 0.280 ;
    END
  END p2_axi_rdata_11
  PIN p2_axi_rdata_12
    DIRECTION INPUT ;
    USE SIGNAL ;
    PORT
      LAYER met2 ;
        RECT 135.330 0.000 135.610 0.280 ;
    END
  END p2_axi_rdata_12
  PIN p2_axi_rdata_13
    DIRECTION INPUT ;
    USE SIGNAL ;
    PORT
      LAYER met2 ;
        RECT 84.730 0.000 85.010 0.280 ;
    END
  END p2_axi_rdata_13
  PIN p2_axi_rdata_14
    DIRECTION INPUT ;
    USE SIGNAL ;
    PORT
      LAYER met2 ;
        RECT 89.330 0.000 89.610 0.280 ;
    END
  END p2_axi_rdata_14
  PIN p2_axi_rdata_15
    DIRECTION INPUT ;
    USE SIGNAL ;
    PORT
      LAYER met2 ;
        RECT 96.690 0.000 96.970 0.280 ;
    END
  END p2_axi_rdata_15
  PIN p2_axi_rdata_16
    DIRECTION INPUT ;
    USE SIGNAL ;
    PORT
      LAYER met2 ;
        RECT 91.170 0.000 91.450 0.280 ;
    END
  END p2_axi_rdata_16
  PIN p2_axi_rdata_17
    DIRECTION INPUT ;
    USE SIGNAL ;
    PORT
      LAYER met2 ;
        RECT 88.410 0.000 88.690 0.280 ;
    END
  END p2_axi_rdata_17
  PIN p2_axi_rdata_18
    DIRECTION INPUT ;
    USE SIGNAL ;
    PORT
      LAYER met2 ;
        RECT 93.010 0.000 93.290 0.280 ;
    END
  END p2_axi_rdata_18
  PIN p2_axi_rdata_19
    DIRECTION INPUT ;
    USE SIGNAL ;
    PORT
      LAYER met2 ;
        RECT 5.610 0.000 5.890 0.280 ;
    END
  END p2_axi_rdata_19
  PIN p2_axi_rdata_2
    DIRECTION INPUT ;
    USE SIGNAL ;
    PORT
      LAYER met2 ;
        RECT 94.850 0.000 95.130 0.280 ;
    END
  END p2_axi_rdata_2
  PIN p2_axi_rdata_20
    DIRECTION INPUT ;
    USE SIGNAL ;
    PORT
      LAYER met2 ;
        RECT 92.090 0.000 92.370 0.280 ;
    END
  END p2_axi_rdata_20
  PIN p2_axi_rdata_21
    DIRECTION INPUT ;
    USE SIGNAL ;
    PORT
      LAYER met2 ;
        RECT 105.890 0.000 106.170 0.280 ;
    END
  END p2_axi_rdata_21
  PIN p2_axi_rdata_22
    DIRECTION INPUT ;
    USE SIGNAL ;
    PORT
      LAYER met2 ;
        RECT 116.010 0.000 116.290 0.280 ;
    END
  END p2_axi_rdata_22
  PIN p2_axi_rdata_23
    DIRECTION INPUT ;
    USE SIGNAL ;
    PORT
      LAYER met2 ;
        RECT 115.090 0.000 115.370 0.280 ;
    END
  END p2_axi_rdata_23
  PIN p2_axi_rdata_24
    DIRECTION INPUT ;
    USE SIGNAL ;
    PORT
      LAYER met2 ;
        RECT 95.770 0.000 96.050 0.280 ;
    END
  END p2_axi_rdata_24
  PIN p2_axi_rdata_25
    DIRECTION INPUT ;
    USE SIGNAL ;
    PORT
      LAYER met2 ;
        RECT 142.690 0.000 142.970 0.280 ;
    END
  END p2_axi_rdata_25
  PIN p2_axi_rdata_26
    DIRECTION INPUT ;
    USE SIGNAL ;
    PORT
      LAYER met2 ;
        RECT 3.770 0.000 4.050 0.280 ;
    END
  END p2_axi_rdata_26
  PIN p2_axi_rdata_27
    DIRECTION INPUT ;
    USE SIGNAL ;
    PORT
      LAYER met2 ;
        RECT 102.210 0.000 102.490 0.280 ;
    END
  END p2_axi_rdata_27
  PIN p2_axi_rdata_28
    DIRECTION INPUT ;
    USE SIGNAL ;
    PORT
      LAYER met2 ;
        RECT 117.850 0.000 118.130 0.280 ;
    END
  END p2_axi_rdata_28
  PIN p2_axi_rdata_29
    DIRECTION INPUT ;
    USE SIGNAL ;
    PORT
      LAYER met2 ;
        RECT 104.050 0.000 104.330 0.280 ;
    END
  END p2_axi_rdata_29
  PIN p2_axi_rdata_3
    DIRECTION INPUT ;
    USE SIGNAL ;
    PORT
      LAYER met2 ;
        RECT 104.970 0.000 105.250 0.280 ;
    END
  END p2_axi_rdata_3
  PIN p2_axi_rdata_30
    DIRECTION INPUT ;
    USE SIGNAL ;
    PORT
      LAYER met2 ;
        RECT 122.450 0.000 122.730 0.280 ;
    END
  END p2_axi_rdata_30
  PIN p2_axi_rdata_31
    DIRECTION INPUT ;
    USE SIGNAL ;
    PORT
      LAYER met2 ;
        RECT 113.250 0.000 113.530 0.280 ;
    END
  END p2_axi_rdata_31
  PIN p2_axi_rdata_4
    DIRECTION INPUT ;
    USE SIGNAL ;
    PORT
      LAYER met2 ;
        RECT 107.730 0.000 108.010 0.280 ;
    END
  END p2_axi_rdata_4
  PIN p2_axi_rdata_5
    DIRECTION INPUT ;
    USE SIGNAL ;
    PORT
      LAYER met2 ;
        RECT 141.770 0.000 142.050 0.280 ;
    END
  END p2_axi_rdata_5
  PIN p2_axi_rdata_6
    DIRECTION INPUT ;
    USE SIGNAL ;
    PORT
      LAYER met2 ;
        RECT 151.890 0.000 152.170 0.280 ;
    END
  END p2_axi_rdata_6
  PIN p2_axi_rdata_7
    DIRECTION INPUT ;
    USE SIGNAL ;
    PORT
      LAYER met2 ;
        RECT 144.530 0.000 144.810 0.280 ;
    END
  END p2_axi_rdata_7
  PIN p2_axi_rdata_8
    DIRECTION INPUT ;
    USE SIGNAL ;
    PORT
      LAYER met2 ;
        RECT 111.410 0.000 111.690 0.280 ;
    END
  END p2_axi_rdata_8
  PIN p2_axi_rdata_9
    DIRECTION INPUT ;
    USE SIGNAL ;
    PORT
      LAYER met2 ;
        RECT 112.330 0.000 112.610 0.280 ;
    END
  END p2_axi_rdata_9
  PIN p2_axi_rready
    DIRECTION OUTPUT ;
    USE SIGNAL ;
    ANTENNAGATEAREA 0.434700 ;
    ANTENNADIFFAREA 0.775300 ;
    PORT
      LAYER met3 ;
        RECT 0.000 83.000 0.600 83.600 ;
    END
  END p2_axi_rready
  PIN p2_axi_rresp_0
    DIRECTION INPUT ;
    USE SIGNAL ;
    PORT
      LAYER met2 ;
        RECT 119.690 0.000 119.970 0.280 ;
    END
  END p2_axi_rresp_0
  PIN p2_axi_rresp_1
    DIRECTION INPUT ;
    USE SIGNAL ;
    PORT
      LAYER met2 ;
        RECT 110.490 0.000 110.770 0.280 ;
    END
  END p2_axi_rresp_1
  PIN p2_axi_rvalid
    DIRECTION INPUT ;
    USE SIGNAL ;
    PORT
      LAYER met2 ;
        RECT 157.410 0.000 157.690 0.280 ;
    END
  END p2_axi_rvalid
  PIN p2_axi_wdata_0
    DIRECTION OUTPUT ;
    USE SIGNAL ;
    ANTENNAGATEAREA 0.434700 ;
    ANTENNADIFFAREA 1.137600 ;
    PORT
      LAYER met2 ;
        RECT 58.970 170.550 59.250 170.830 ;
    END
  END p2_axi_wdata_0
  PIN p2_axi_wdata_1
    DIRECTION OUTPUT ;
    USE SIGNAL ;
    ANTENNAGATEAREA 0.434700 ;
    ANTENNADIFFAREA 1.137600 ;
    PORT
      LAYER met3 ;
        RECT 0.000 24.520 0.600 25.120 ;
    END
  END p2_axi_wdata_1
  PIN p2_axi_wdata_10
    DIRECTION OUTPUT ;
    USE SIGNAL ;
    ANTENNAGATEAREA 0.434700 ;
    ANTENNADIFFAREA 1.137600 ;
    PORT
      LAYER met2 ;
        RECT 49.770 170.550 50.050 170.830 ;
    END
  END p2_axi_wdata_10
  PIN p2_axi_wdata_11
    DIRECTION OUTPUT ;
    USE SIGNAL ;
    ANTENNAGATEAREA 0.434700 ;
    ANTENNADIFFAREA 1.137600 ;
    PORT
      LAYER met3 ;
        RECT 0.000 35.400 0.600 36.000 ;
    END
  END p2_axi_wdata_11
  PIN p2_axi_wdata_12
    DIRECTION OUTPUT ;
    USE SIGNAL ;
    ANTENNAGATEAREA 0.434700 ;
    ANTENNADIFFAREA 1.137600 ;
    PORT
      LAYER met3 ;
        RECT 0.000 43.560 0.600 44.160 ;
    END
  END p2_axi_wdata_12
  PIN p2_axi_wdata_13
    DIRECTION OUTPUT ;
    USE SIGNAL ;
    ANTENNAGATEAREA 0.434700 ;
    ANTENNADIFFAREA 1.137600 ;
    PORT
      LAYER met3 ;
        RECT 0.000 104.760 0.600 105.360 ;
    END
  END p2_axi_wdata_13
  PIN p2_axi_wdata_14
    DIRECTION OUTPUT ;
    USE SIGNAL ;
    ANTENNAGATEAREA 0.434700 ;
    ANTENNADIFFAREA 1.137600 ;
    PORT
      LAYER met2 ;
        RECT 78.290 170.550 78.570 170.830 ;
    END
  END p2_axi_wdata_14
  PIN p2_axi_wdata_15
    DIRECTION OUTPUT ;
    USE SIGNAL ;
    ANTENNAGATEAREA 0.434700 ;
    ANTENNADIFFAREA 1.137600 ;
    PORT
      LAYER met3 ;
        RECT 159.510 112.920 160.110 113.520 ;
    END
  END p2_axi_wdata_15
  PIN p2_axi_wdata_16
    DIRECTION OUTPUT ;
    USE SIGNAL ;
    ANTENNAGATEAREA 0.434700 ;
    ANTENNADIFFAREA 1.137600 ;
    PORT
      LAYER met3 ;
        RECT 0.000 76.200 0.600 76.800 ;
    END
  END p2_axi_wdata_16
  PIN p2_axi_wdata_17
    DIRECTION OUTPUT ;
    USE SIGNAL ;
    ANTENNAGATEAREA 0.434700 ;
    ANTENNADIFFAREA 1.137600 ;
    PORT
      LAYER met2 ;
        RECT 37.810 170.550 38.090 170.830 ;
    END
  END p2_axi_wdata_17
  PIN p2_axi_wdata_18
    DIRECTION OUTPUT ;
    USE SIGNAL ;
    ANTENNAGATEAREA 0.434700 ;
    ANTENNADIFFAREA 1.137600 ;
    PORT
      LAYER met2 ;
        RECT 43.330 170.550 43.610 170.830 ;
    END
  END p2_axi_wdata_18
  PIN p2_axi_wdata_19
    DIRECTION OUTPUT ;
    USE SIGNAL ;
    ANTENNAGATEAREA 0.434700 ;
    ANTENNADIFFAREA 1.137600 ;
    PORT
      LAYER met3 ;
        RECT 0.000 108.840 0.600 109.440 ;
    END
  END p2_axi_wdata_19
  PIN p2_axi_wdata_2
    DIRECTION OUTPUT ;
    USE SIGNAL ;
    ANTENNAGATEAREA 0.434700 ;
    ANTENNADIFFAREA 1.137600 ;
    PORT
      LAYER met2 ;
        RECT 84.730 170.550 85.010 170.830 ;
    END
  END p2_axi_wdata_2
  PIN p2_axi_wdata_20
    DIRECTION OUTPUT ;
    USE SIGNAL ;
    ANTENNAGATEAREA 0.434700 ;
    ANTENNADIFFAREA 1.137600 ;
    PORT
      LAYER met3 ;
        RECT 0.000 12.280 0.600 12.880 ;
    END
  END p2_axi_wdata_20
  PIN p2_axi_wdata_21
    DIRECTION OUTPUT ;
    USE SIGNAL ;
    ANTENNAGATEAREA 0.434700 ;
    ANTENNADIFFAREA 1.137600 ;
    PORT
      LAYER met3 ;
        RECT 0.000 80.280 0.600 80.880 ;
    END
  END p2_axi_wdata_21
  PIN p2_axi_wdata_22
    DIRECTION OUTPUT ;
    USE SIGNAL ;
    ANTENNAGATEAREA 0.434700 ;
    ANTENNADIFFAREA 1.137600 ;
    PORT
      LAYER met3 ;
        RECT 0.000 119.720 0.600 120.320 ;
    END
  END p2_axi_wdata_22
  PIN p2_axi_wdata_23
    DIRECTION OUTPUT ;
    USE SIGNAL ;
    ANTENNAGATEAREA 0.434700 ;
    ANTENNADIFFAREA 1.137600 ;
    PORT
      LAYER met2 ;
        RECT 95.770 170.550 96.050 170.830 ;
    END
  END p2_axi_wdata_23
  PIN p2_axi_wdata_24
    DIRECTION OUTPUT ;
    USE SIGNAL ;
    ANTENNAGATEAREA 0.434700 ;
    ANTENNADIFFAREA 1.137600 ;
    PORT
      LAYER met2 ;
        RECT 67.250 0.000 67.530 0.280 ;
    END
  END p2_axi_wdata_24
  PIN p2_axi_wdata_25
    DIRECTION OUTPUT ;
    USE SIGNAL ;
    ANTENNAGATEAREA 0.434700 ;
    ANTENNADIFFAREA 1.137600 ;
    PORT
      LAYER met2 ;
        RECT 53.450 170.550 53.730 170.830 ;
    END
  END p2_axi_wdata_25
  PIN p2_axi_wdata_26
    DIRECTION OUTPUT ;
    USE SIGNAL ;
    ANTENNAGATEAREA 0.434700 ;
    ANTENNADIFFAREA 1.137600 ;
    PORT
      LAYER met2 ;
        RECT 101.290 170.550 101.570 170.830 ;
    END
  END p2_axi_wdata_26
  PIN p2_axi_wdata_27
    DIRECTION OUTPUT ;
    USE SIGNAL ;
    ANTENNAGATEAREA 0.434700 ;
    ANTENNADIFFAREA 1.137600 ;
    PORT
      LAYER met3 ;
        RECT 159.510 108.840 160.110 109.440 ;
    END
  END p2_axi_wdata_27
  PIN p2_axi_wdata_28
    DIRECTION OUTPUT ;
    USE SIGNAL ;
    ANTENNAGATEAREA 0.434700 ;
    ANTENNADIFFAREA 1.137600 ;
    PORT
      LAYER met3 ;
        RECT 0.000 103.400 0.600 104.000 ;
    END
  END p2_axi_wdata_28
  PIN p2_axi_wdata_29
    DIRECTION OUTPUT ;
    USE SIGNAL ;
    ANTENNAGATEAREA 0.434700 ;
    ANTENNADIFFAREA 1.137600 ;
    PORT
      LAYER met2 ;
        RECT 86.570 170.550 86.850 170.830 ;
    END
  END p2_axi_wdata_29
  PIN p2_axi_wdata_3
    DIRECTION OUTPUT ;
    USE SIGNAL ;
    ANTENNAGATEAREA 0.434700 ;
    ANTENNADIFFAREA 1.137600 ;
    PORT
      LAYER met2 ;
        RECT 62.650 170.550 62.930 170.830 ;
    END
  END p2_axi_wdata_3
  PIN p2_axi_wdata_30
    DIRECTION OUTPUT ;
    USE SIGNAL ;
    ANTENNAGATEAREA 0.434700 ;
    ANTENNADIFFAREA 1.137600 ;
    PORT
      LAYER met3 ;
        RECT 0.000 93.880 0.600 94.480 ;
    END
  END p2_axi_wdata_30
  PIN p2_axi_wdata_31
    DIRECTION OUTPUT ;
    USE SIGNAL ;
    ANTENNAGATEAREA 0.434700 ;
    ANTENNADIFFAREA 1.137600 ;
    PORT
      LAYER met3 ;
        RECT 159.510 121.080 160.110 121.680 ;
    END
  END p2_axi_wdata_31
  PIN p2_axi_wdata_4
    DIRECTION OUTPUT ;
    USE SIGNAL ;
    ANTENNAGATEAREA 0.434700 ;
    ANTENNADIFFAREA 1.137600 ;
    PORT
      LAYER met3 ;
        RECT 0.000 137.400 0.600 138.000 ;
    END
  END p2_axi_wdata_4
  PIN p2_axi_wdata_5
    DIRECTION OUTPUT ;
    USE SIGNAL ;
    ANTENNAGATEAREA 0.434700 ;
    ANTENNADIFFAREA 1.137600 ;
    PORT
      LAYER met2 ;
        RECT 38.730 0.000 39.010 0.280 ;
    END
  END p2_axi_wdata_5
  PIN p2_axi_wdata_6
    DIRECTION OUTPUT ;
    USE SIGNAL ;
    ANTENNAGATEAREA 0.434700 ;
    ANTENNADIFFAREA 1.137600 ;
    PORT
      LAYER met2 ;
        RECT 72.770 170.550 73.050 170.830 ;
    END
  END p2_axi_wdata_6
  PIN p2_axi_wdata_7
    DIRECTION OUTPUT ;
    USE SIGNAL ;
    ANTENNAGATEAREA 0.434700 ;
    ANTENNADIFFAREA 1.137600 ;
    PORT
      LAYER met3 ;
        RECT 0.000 36.760 0.600 37.360 ;
    END
  END p2_axi_wdata_7
  PIN p2_axi_wdata_8
    DIRECTION OUTPUT ;
    USE SIGNAL ;
    ANTENNAGATEAREA 0.434700 ;
    ANTENNADIFFAREA 1.137600 ;
    PORT
      LAYER met2 ;
        RECT 79.210 0.000 79.490 0.280 ;
    END
  END p2_axi_wdata_8
  PIN p2_axi_wdata_9
    DIRECTION OUTPUT ;
    USE SIGNAL ;
    ANTENNAGATEAREA 0.434700 ;
    ANTENNADIFFAREA 1.137600 ;
    PORT
      LAYER met2 ;
        RECT 55.290 170.550 55.570 170.830 ;
    END
  END p2_axi_wdata_9
  PIN p2_axi_wready
    DIRECTION INPUT ;
    USE SIGNAL ;
    PORT
      LAYER met2 ;
        RECT 132.570 0.000 132.850 0.280 ;
    END
  END p2_axi_wready
  PIN p2_axi_wstrb_0
    DIRECTION OUTPUT ;
    USE SIGNAL ;
    ANTENNAGATEAREA 0.434700 ;
    ANTENNADIFFAREA 1.137600 ;
    PORT
      LAYER met2 ;
        RECT 116.010 170.550 116.290 170.830 ;
    END
  END p2_axi_wstrb_0
  PIN p2_axi_wstrb_1
    DIRECTION OUTPUT ;
    USE SIGNAL ;
    ANTENNAGATEAREA 0.434700 ;
    ANTENNADIFFAREA 1.137600 ;
    PORT
      LAYER met2 ;
        RECT 64.490 170.550 64.770 170.830 ;
    END
  END p2_axi_wstrb_1
  PIN p2_axi_wstrb_2
    DIRECTION OUTPUT ;
    USE SIGNAL ;
    ANTENNAGATEAREA 0.434700 ;
    ANTENNADIFFAREA 1.137600 ;
    PORT
      LAYER met2 ;
        RECT 56.210 0.000 56.490 0.280 ;
    END
  END p2_axi_wstrb_2
  PIN p2_axi_wstrb_3
    DIRECTION OUTPUT ;
    USE SIGNAL ;
    ANTENNAGATEAREA 0.434700 ;
    ANTENNADIFFAREA 1.137600 ;
    PORT
      LAYER met2 ;
        RECT 93.930 170.550 94.210 170.830 ;
    END
  END p2_axi_wstrb_3
  PIN p2_axi_wvalid
    DIRECTION OUTPUT ;
    USE SIGNAL ;
    ANTENNAGATEAREA 0.434700 ;
    ANTENNADIFFAREA 0.775300 ;
    PORT
      LAYER met3 ;
        RECT 0.000 77.560 0.600 78.160 ;
    END
  END p2_axi_wvalid
  PIN p3_axi_araddr_0
    DIRECTION OUTPUT ;
    USE SIGNAL ;
    ANTENNAGATEAREA 0.434700 ;
    ANTENNADIFFAREA 1.137600 ;
    PORT
      LAYER met3 ;
        RECT 0.000 129.240 0.600 129.840 ;
    END
  END p3_axi_araddr_0
  PIN p3_axi_araddr_1
    DIRECTION OUTPUT ;
    USE SIGNAL ;
    ANTENNAGATEAREA 0.434700 ;
    ANTENNADIFFAREA 1.137600 ;
    PORT
      LAYER met2 ;
        RECT 53.450 0.000 53.730 0.280 ;
    END
  END p3_axi_araddr_1
  PIN p3_axi_araddr_10
    DIRECTION OUTPUT ;
    USE SIGNAL ;
    ANTENNAGATEAREA 0.434700 ;
    ANTENNADIFFAREA 1.137600 ;
    PORT
      LAYER met3 ;
        RECT 0.000 92.520 0.600 93.120 ;
    END
  END p3_axi_araddr_10
  PIN p3_axi_araddr_11
    DIRECTION OUTPUT ;
    USE SIGNAL ;
    ANTENNAGATEAREA 0.434700 ;
    ANTENNADIFFAREA 1.137600 ;
    PORT
      LAYER met3 ;
        RECT 0.000 63.960 0.600 64.560 ;
    END
  END p3_axi_araddr_11
  PIN p3_axi_araddr_2
    DIRECTION OUTPUT ;
    USE SIGNAL ;
    ANTENNAGATEAREA 0.434700 ;
    ANTENNADIFFAREA 1.137600 ;
    PORT
      LAYER met3 ;
        RECT 159.510 122.440 160.110 123.040 ;
    END
  END p3_axi_araddr_2
  PIN p3_axi_araddr_3
    DIRECTION OUTPUT ;
    USE SIGNAL ;
    ANTENNAGATEAREA 0.434700 ;
    ANTENNADIFFAREA 1.137600 ;
    PORT
      LAYER met2 ;
        RECT 70.010 170.550 70.290 170.830 ;
    END
  END p3_axi_araddr_3
  PIN p3_axi_araddr_4
    DIRECTION OUTPUT ;
    USE SIGNAL ;
    ANTENNAGATEAREA 0.434700 ;
    ANTENNADIFFAREA 1.137600 ;
    PORT
      LAYER met2 ;
        RECT 72.770 0.000 73.050 0.280 ;
    END
  END p3_axi_araddr_4
  PIN p3_axi_araddr_5
    DIRECTION OUTPUT ;
    USE SIGNAL ;
    ANTENNAGATEAREA 0.434700 ;
    ANTENNADIFFAREA 1.137600 ;
    PORT
      LAYER met3 ;
        RECT 159.510 99.320 160.110 99.920 ;
    END
  END p3_axi_araddr_5
  PIN p3_axi_araddr_6
    DIRECTION OUTPUT ;
    USE SIGNAL ;
    ANTENNAGATEAREA 0.434700 ;
    ANTENNADIFFAREA 1.137600 ;
    PORT
      LAYER met2 ;
        RECT 74.610 170.550 74.890 170.830 ;
    END
  END p3_axi_araddr_6
  PIN p3_axi_araddr_7
    DIRECTION OUTPUT ;
    USE SIGNAL ;
    ANTENNAGATEAREA 0.434700 ;
    ANTENNADIFFAREA 1.137600 ;
    PORT
      LAYER met2 ;
        RECT 90.250 170.550 90.530 170.830 ;
    END
  END p3_axi_araddr_7
  PIN p3_axi_araddr_8
    DIRECTION OUTPUT ;
    USE SIGNAL ;
    ANTENNAGATEAREA 0.434700 ;
    ANTENNADIFFAREA 1.137600 ;
    PORT
      LAYER met2 ;
        RECT 124.290 170.550 124.570 170.830 ;
    END
  END p3_axi_araddr_8
  PIN p3_axi_araddr_9
    DIRECTION OUTPUT ;
    USE SIGNAL ;
    ANTENNAGATEAREA 0.434700 ;
    ANTENNADIFFAREA 1.137600 ;
    PORT
      LAYER met3 ;
        RECT 0.000 114.280 0.600 114.880 ;
    END
  END p3_axi_araddr_9
  PIN p3_axi_arready
    DIRECTION INPUT ;
    USE SIGNAL ;
    PORT
      LAYER met2 ;
        RECT 116.930 0.000 117.210 0.280 ;
    END
  END p3_axi_arready
  PIN p3_axi_arvalid
    DIRECTION OUTPUT ;
    USE SIGNAL ;
    ANTENNAGATEAREA 0.434700 ;
    ANTENNADIFFAREA 0.775300 ;
    PORT
      LAYER met3 ;
        RECT 0.000 87.080 0.600 87.680 ;
    END
  END p3_axi_arvalid
  PIN p3_axi_awaddr_0
    DIRECTION OUTPUT ;
    USE SIGNAL ;
    ANTENNAGATEAREA 0.434700 ;
    ANTENNADIFFAREA 1.137600 ;
    PORT
      LAYER met2 ;
        RECT 127.970 170.550 128.250 170.830 ;
    END
  END p3_axi_awaddr_0
  PIN p3_axi_awaddr_1
    DIRECTION OUTPUT ;
    USE SIGNAL ;
    ANTENNAGATEAREA 0.434700 ;
    ANTENNADIFFAREA 1.137600 ;
    PORT
      LAYER met3 ;
        RECT 0.000 100.680 0.600 101.280 ;
    END
  END p3_axi_awaddr_1
  PIN p3_axi_awaddr_10
    DIRECTION OUTPUT ;
    USE SIGNAL ;
    ANTENNAGATEAREA 0.434700 ;
    ANTENNADIFFAREA 1.137600 ;
    PORT
      LAYER met3 ;
        RECT 0.000 17.720 0.600 18.320 ;
    END
  END p3_axi_awaddr_10
  PIN p3_axi_awaddr_11
    DIRECTION OUTPUT ;
    USE SIGNAL ;
    ANTENNAGATEAREA 0.434700 ;
    ANTENNADIFFAREA 1.137600 ;
    PORT
      LAYER met2 ;
        RECT 104.050 170.550 104.330 170.830 ;
    END
  END p3_axi_awaddr_11
  PIN p3_axi_awaddr_2
    DIRECTION OUTPUT ;
    USE SIGNAL ;
    ANTENNAGATEAREA 0.434700 ;
    ANTENNADIFFAREA 1.137600 ;
    PORT
      LAYER met2 ;
        RECT 45.170 0.000 45.450 0.280 ;
    END
  END p3_axi_awaddr_2
  PIN p3_axi_awaddr_3
    DIRECTION OUTPUT ;
    USE SIGNAL ;
    ANTENNAGATEAREA 0.434700 ;
    ANTENNADIFFAREA 1.137600 ;
    PORT
      LAYER met2 ;
        RECT 41.490 0.000 41.770 0.280 ;
    END
  END p3_axi_awaddr_3
  PIN p3_axi_awaddr_4
    DIRECTION OUTPUT ;
    USE SIGNAL ;
    ANTENNAGATEAREA 0.434700 ;
    ANTENNADIFFAREA 1.137600 ;
    PORT
      LAYER met3 ;
        RECT 0.000 70.760 0.600 71.360 ;
    END
  END p3_axi_awaddr_4
  PIN p3_axi_awaddr_5
    DIRECTION OUTPUT ;
    USE SIGNAL ;
    ANTENNAGATEAREA 0.434700 ;
    ANTENNADIFFAREA 1.137600 ;
    PORT
      LAYER met3 ;
        RECT 159.510 93.880 160.110 94.480 ;
    END
  END p3_axi_awaddr_5
  PIN p3_axi_awaddr_6
    DIRECTION OUTPUT ;
    USE SIGNAL ;
    ANTENNAGATEAREA 0.434700 ;
    ANTENNADIFFAREA 1.137600 ;
    PORT
      LAYER met3 ;
        RECT 159.510 106.120 160.110 106.720 ;
    END
  END p3_axi_awaddr_6
  PIN p3_axi_awaddr_7
    DIRECTION OUTPUT ;
    USE SIGNAL ;
    ANTENNAGATEAREA 0.434700 ;
    ANTENNADIFFAREA 1.137600 ;
    PORT
      LAYER met3 ;
        RECT 0.000 5.480 0.600 6.080 ;
    END
  END p3_axi_awaddr_7
  PIN p3_axi_awaddr_8
    DIRECTION OUTPUT ;
    USE SIGNAL ;
    ANTENNAGATEAREA 0.434700 ;
    ANTENNADIFFAREA 1.137600 ;
    PORT
      LAYER met3 ;
        RECT 0.000 149.640 0.600 150.240 ;
    END
  END p3_axi_awaddr_8
  PIN p3_axi_awaddr_9
    DIRECTION OUTPUT ;
    USE SIGNAL ;
    ANTENNAGATEAREA 0.434700 ;
    ANTENNADIFFAREA 1.137600 ;
    PORT
      LAYER met2 ;
        RECT 113.250 170.550 113.530 170.830 ;
    END
  END p3_axi_awaddr_9
  PIN p3_axi_awready
    DIRECTION INPUT ;
    USE SIGNAL ;
    PORT
      LAYER met2 ;
        RECT 114.170 0.000 114.450 0.280 ;
    END
  END p3_axi_awready
  PIN p3_axi_awvalid
    DIRECTION OUTPUT ;
    USE SIGNAL ;
    ANTENNAGATEAREA 0.434700 ;
    ANTENNADIFFAREA 0.775300 ;
    PORT
      LAYER met2 ;
        RECT 58.970 0.000 59.250 0.280 ;
    END
  END p3_axi_awvalid
  PIN p3_axi_bready
    DIRECTION OUTPUT ;
    USE SIGNAL ;
    ANTENNAGATEAREA 0.434700 ;
    ANTENNADIFFAREA 0.775300 ;
    PORT
      LAYER met3 ;
        RECT 0.000 84.360 0.600 84.960 ;
    END
  END p3_axi_bready
  PIN p3_axi_bresp_0
    DIRECTION INPUT ;
    USE SIGNAL ;
    PORT
      LAYER met2 ;
        RECT 118.770 0.000 119.050 0.280 ;
    END
  END p3_axi_bresp_0
  PIN p3_axi_bresp_1
    DIRECTION INPUT ;
    USE SIGNAL ;
    PORT
      LAYER met2 ;
        RECT 126.130 0.000 126.410 0.280 ;
    END
  END p3_axi_bresp_1
  PIN p3_axi_bvalid
    DIRECTION INPUT ;
    USE SIGNAL ;
    PORT
      LAYER met2 ;
        RECT 120.610 0.000 120.890 0.280 ;
    END
  END p3_axi_bvalid
  PIN p3_axi_rdata_0
    DIRECTION INPUT ;
    USE SIGNAL ;
    PORT
      LAYER met2 ;
        RECT 136.250 0.000 136.530 0.280 ;
    END
  END p3_axi_rdata_0
  PIN p3_axi_rdata_1
    DIRECTION INPUT ;
    USE SIGNAL ;
    PORT
      LAYER met2 ;
        RECT 139.010 0.000 139.290 0.280 ;
    END
  END p3_axi_rdata_1
  PIN p3_axi_rdata_10
    DIRECTION INPUT ;
    USE SIGNAL ;
    PORT
      LAYER met2 ;
        RECT 123.370 0.000 123.650 0.280 ;
    END
  END p3_axi_rdata_10
  PIN p3_axi_rdata_11
    DIRECTION INPUT ;
    USE SIGNAL ;
    PORT
      LAYER met2 ;
        RECT 133.490 0.000 133.770 0.280 ;
    END
  END p3_axi_rdata_11
  PIN p3_axi_rdata_12
    DIRECTION INPUT ;
    USE SIGNAL ;
    PORT
      LAYER met2 ;
        RECT 121.530 0.000 121.810 0.280 ;
    END
  END p3_axi_rdata_12
  PIN p3_axi_rdata_13
    DIRECTION INPUT ;
    USE SIGNAL ;
    PORT
      LAYER met2 ;
        RECT 156.490 0.000 156.770 0.280 ;
    END
  END p3_axi_rdata_13
  PIN p3_axi_rdata_14
    DIRECTION INPUT ;
    USE SIGNAL ;
    PORT
      LAYER met2 ;
        RECT 127.050 0.000 127.330 0.280 ;
    END
  END p3_axi_rdata_14
  PIN p3_axi_rdata_15
    DIRECTION INPUT ;
    USE SIGNAL ;
    PORT
      LAYER met3 ;
        RECT 159.510 129.240 160.110 129.840 ;
    END
  END p3_axi_rdata_15
  PIN p3_axi_rdata_16
    DIRECTION INPUT ;
    USE SIGNAL ;
    PORT
      LAYER met3 ;
        RECT 159.510 155.080 160.110 155.680 ;
    END
  END p3_axi_rdata_16
  PIN p3_axi_rdata_17
    DIRECTION INPUT ;
    USE SIGNAL ;
    PORT
      LAYER met3 ;
        RECT 159.510 68.040 160.110 68.640 ;
    END
  END p3_axi_rdata_17
  PIN p3_axi_rdata_18
    DIRECTION INPUT ;
    USE SIGNAL ;
    PORT
      LAYER met3 ;
        RECT 159.510 16.360 160.110 16.960 ;
    END
  END p3_axi_rdata_18
  PIN p3_axi_rdata_19
    DIRECTION INPUT ;
    USE SIGNAL ;
    PORT
      LAYER met3 ;
        RECT 159.510 15.000 160.110 15.600 ;
    END
  END p3_axi_rdata_19
  PIN p3_axi_rdata_2
    DIRECTION INPUT ;
    USE SIGNAL ;
    PORT
      LAYER met3 ;
        RECT 159.510 42.200 160.110 42.800 ;
    END
  END p3_axi_rdata_2
  PIN p3_axi_rdata_20
    DIRECTION INPUT ;
    USE SIGNAL ;
    PORT
      LAYER met3 ;
        RECT 159.510 165.960 160.110 166.560 ;
    END
  END p3_axi_rdata_20
  PIN p3_axi_rdata_21
    DIRECTION INPUT ;
    USE SIGNAL ;
    PORT
      LAYER met3 ;
        RECT 159.510 81.640 160.110 82.240 ;
    END
  END p3_axi_rdata_21
  PIN p3_axi_rdata_22
    DIRECTION INPUT ;
    USE SIGNAL ;
    PORT
      LAYER met3 ;
        RECT 159.510 35.400 160.110 36.000 ;
    END
  END p3_axi_rdata_22
  PIN p3_axi_rdata_23
    DIRECTION INPUT ;
    USE SIGNAL ;
    PORT
      LAYER met3 ;
        RECT 159.510 20.440 160.110 21.040 ;
    END
  END p3_axi_rdata_23
  PIN p3_axi_rdata_24
    DIRECTION INPUT ;
    USE SIGNAL ;
    PORT
      LAYER met3 ;
        RECT 159.510 43.560 160.110 44.160 ;
    END
  END p3_axi_rdata_24
  PIN p3_axi_rdata_25
    DIRECTION INPUT ;
    USE SIGNAL ;
    PORT
      LAYER met3 ;
        RECT 159.510 36.760 160.110 37.360 ;
    END
  END p3_axi_rdata_25
  PIN p3_axi_rdata_26
    DIRECTION INPUT ;
    USE SIGNAL ;
    PORT
      LAYER met3 ;
        RECT 159.510 39.480 160.110 40.080 ;
    END
  END p3_axi_rdata_26
  PIN p3_axi_rdata_27
    DIRECTION INPUT ;
    USE SIGNAL ;
    PORT
      LAYER met3 ;
        RECT 159.510 80.280 160.110 80.880 ;
    END
  END p3_axi_rdata_27
  PIN p3_axi_rdata_28
    DIRECTION INPUT ;
    USE SIGNAL ;
    PORT
      LAYER met3 ;
        RECT 159.510 23.160 160.110 23.760 ;
    END
  END p3_axi_rdata_28
  PIN p3_axi_rdata_29
    DIRECTION INPUT ;
    USE SIGNAL ;
    PORT
      LAYER met3 ;
        RECT 159.510 58.520 160.110 59.120 ;
    END
  END p3_axi_rdata_29
  PIN p3_axi_rdata_3
    DIRECTION INPUT ;
    USE SIGNAL ;
    PORT
      LAYER met3 ;
        RECT 159.510 32.680 160.110 33.280 ;
    END
  END p3_axi_rdata_3
  PIN p3_axi_rdata_30
    DIRECTION INPUT ;
    USE SIGNAL ;
    PORT
      LAYER met3 ;
        RECT 159.510 50.360 160.110 50.960 ;
    END
  END p3_axi_rdata_30
  PIN p3_axi_rdata_31
    DIRECTION INPUT ;
    USE SIGNAL ;
    PORT
      LAYER met3 ;
        RECT 159.510 28.600 160.110 29.200 ;
    END
  END p3_axi_rdata_31
  PIN p3_axi_rdata_4
    DIRECTION INPUT ;
    USE SIGNAL ;
    PORT
      LAYER met3 ;
        RECT 159.510 29.960 160.110 30.560 ;
    END
  END p3_axi_rdata_4
  PIN p3_axi_rdata_5
    DIRECTION INPUT ;
    USE SIGNAL ;
    PORT
      LAYER met3 ;
        RECT 159.510 141.480 160.110 142.080 ;
    END
  END p3_axi_rdata_5
  PIN p3_axi_rdata_6
    DIRECTION INPUT ;
    USE SIGNAL ;
    PORT
      LAYER met3 ;
        RECT 159.510 151.000 160.110 151.600 ;
    END
  END p3_axi_rdata_6
  PIN p3_axi_rdata_7
    DIRECTION INPUT ;
    USE SIGNAL ;
    PORT
      LAYER met3 ;
        RECT 159.510 34.040 160.110 34.640 ;
    END
  END p3_axi_rdata_7
  PIN p3_axi_rdata_8
    DIRECTION INPUT ;
    USE SIGNAL ;
    PORT
      LAYER met3 ;
        RECT 159.510 145.560 160.110 146.160 ;
    END
  END p3_axi_rdata_8
  PIN p3_axi_rdata_9
    DIRECTION INPUT ;
    USE SIGNAL ;
    PORT
      LAYER met3 ;
        RECT 159.510 78.920 160.110 79.520 ;
    END
  END p3_axi_rdata_9
  PIN p3_axi_rready
    DIRECTION OUTPUT ;
    USE SIGNAL ;
    ANTENNAGATEAREA 0.434700 ;
    ANTENNADIFFAREA 0.775300 ;
    PORT
      LAYER met3 ;
        RECT 0.000 4.120 0.600 4.720 ;
    END
  END p3_axi_rready
  PIN p3_axi_rresp_0
    DIRECTION INPUT ;
    USE SIGNAL ;
    PORT
      LAYER met3 ;
        RECT 159.510 55.800 160.110 56.400 ;
    END
  END p3_axi_rresp_0
  PIN p3_axi_rresp_1
    DIRECTION INPUT ;
    USE SIGNAL ;
    PORT
      LAYER met3 ;
        RECT 159.510 66.680 160.110 67.280 ;
    END
  END p3_axi_rresp_1
  PIN p3_axi_rvalid
    DIRECTION INPUT ;
    USE SIGNAL ;
    PORT
      LAYER met3 ;
        RECT 159.510 83.000 160.110 83.600 ;
    END
  END p3_axi_rvalid
  PIN p3_axi_wdata_0
    DIRECTION OUTPUT ;
    USE SIGNAL ;
    ANTENNAGATEAREA 0.434700 ;
    ANTENNADIFFAREA 1.137600 ;
    PORT
      LAYER met2 ;
        RECT 57.130 170.550 57.410 170.830 ;
    END
  END p3_axi_wdata_0
  PIN p3_axi_wdata_1
    DIRECTION OUTPUT ;
    USE SIGNAL ;
    ANTENNAGATEAREA 0.434700 ;
    ANTENNADIFFAREA 1.137600 ;
    PORT
      LAYER met3 ;
        RECT 0.000 23.160 0.600 23.760 ;
    END
  END p3_axi_wdata_1
  PIN p3_axi_wdata_10
    DIRECTION OUTPUT ;
    USE SIGNAL ;
    ANTENNAGATEAREA 0.434700 ;
    ANTENNADIFFAREA 1.137600 ;
    PORT
      LAYER met2 ;
        RECT 48.850 170.550 49.130 170.830 ;
    END
  END p3_axi_wdata_10
  PIN p3_axi_wdata_11
    DIRECTION OUTPUT ;
    USE SIGNAL ;
    ANTENNAGATEAREA 0.434700 ;
    ANTENNADIFFAREA 1.137600 ;
    PORT
      LAYER met3 ;
        RECT 0.000 44.920 0.600 45.520 ;
    END
  END p3_axi_wdata_11
  PIN p3_axi_wdata_12
    DIRECTION OUTPUT ;
    USE SIGNAL ;
    ANTENNAGATEAREA 0.434700 ;
    ANTENNADIFFAREA 1.137600 ;
    PORT
      LAYER met3 ;
        RECT 0.000 25.880 0.600 26.480 ;
    END
  END p3_axi_wdata_12
  PIN p3_axi_wdata_13
    DIRECTION OUTPUT ;
    USE SIGNAL ;
    ANTENNAGATEAREA 0.434700 ;
    ANTENNADIFFAREA 1.137600 ;
    PORT
      LAYER met3 ;
        RECT 0.000 106.120 0.600 106.720 ;
    END
  END p3_axi_wdata_13
  PIN p3_axi_wdata_14
    DIRECTION OUTPUT ;
    USE SIGNAL ;
    ANTENNAGATEAREA 0.434700 ;
    ANTENNADIFFAREA 1.137600 ;
    PORT
      LAYER met2 ;
        RECT 79.210 170.550 79.490 170.830 ;
    END
  END p3_axi_wdata_14
  PIN p3_axi_wdata_15
    DIRECTION OUTPUT ;
    USE SIGNAL ;
    ANTENNAGATEAREA 0.434700 ;
    ANTENNADIFFAREA 1.137600 ;
    PORT
      LAYER met3 ;
        RECT 159.510 114.280 160.110 114.880 ;
    END
  END p3_axi_wdata_15
  PIN p3_axi_wdata_16
    DIRECTION OUTPUT ;
    USE SIGNAL ;
    ANTENNAGATEAREA 0.434700 ;
    ANTENNADIFFAREA 1.137600 ;
    PORT
      LAYER met3 ;
        RECT 0.000 73.480 0.600 74.080 ;
    END
  END p3_axi_wdata_16
  PIN p3_axi_wdata_17
    DIRECTION OUTPUT ;
    USE SIGNAL ;
    ANTENNAGATEAREA 0.434700 ;
    ANTENNADIFFAREA 1.137600 ;
    PORT
      LAYER met2 ;
        RECT 36.890 170.550 37.170 170.830 ;
    END
  END p3_axi_wdata_17
  PIN p3_axi_wdata_18
    DIRECTION OUTPUT ;
    USE SIGNAL ;
    ANTENNAGATEAREA 0.434700 ;
    ANTENNADIFFAREA 1.137600 ;
    PORT
      LAYER met2 ;
        RECT 41.490 170.550 41.770 170.830 ;
    END
  END p3_axi_wdata_18
  PIN p3_axi_wdata_19
    DIRECTION OUTPUT ;
    USE SIGNAL ;
    ANTENNAGATEAREA 0.434700 ;
    ANTENNADIFFAREA 1.137600 ;
    PORT
      LAYER met3 ;
        RECT 0.000 111.560 0.600 112.160 ;
    END
  END p3_axi_wdata_19
  PIN p3_axi_wdata_2
    DIRECTION OUTPUT ;
    USE SIGNAL ;
    ANTENNAGATEAREA 0.434700 ;
    ANTENNADIFFAREA 1.137600 ;
    PORT
      LAYER met2 ;
        RECT 83.810 170.550 84.090 170.830 ;
    END
  END p3_axi_wdata_2
  PIN p3_axi_wdata_20
    DIRECTION OUTPUT ;
    USE SIGNAL ;
    ANTENNAGATEAREA 0.434700 ;
    ANTENNADIFFAREA 1.137600 ;
    PORT
      LAYER met3 ;
        RECT 0.000 32.680 0.600 33.280 ;
    END
  END p3_axi_wdata_20
  PIN p3_axi_wdata_21
    DIRECTION OUTPUT ;
    USE SIGNAL ;
    ANTENNAGATEAREA 0.434700 ;
    ANTENNADIFFAREA 1.137600 ;
    PORT
      LAYER met3 ;
        RECT 0.000 81.640 0.600 82.240 ;
    END
  END p3_axi_wdata_21
  PIN p3_axi_wdata_22
    DIRECTION OUTPUT ;
    USE SIGNAL ;
    ANTENNAGATEAREA 0.434700 ;
    ANTENNADIFFAREA 1.137600 ;
    PORT
      LAYER met3 ;
        RECT 0.000 121.080 0.600 121.680 ;
    END
  END p3_axi_wdata_22
  PIN p3_axi_wdata_23
    DIRECTION OUTPUT ;
    USE SIGNAL ;
    ANTENNAGATEAREA 0.434700 ;
    ANTENNADIFFAREA 1.137600 ;
    PORT
      LAYER met2 ;
        RECT 96.690 170.550 96.970 170.830 ;
    END
  END p3_axi_wdata_23
  PIN p3_axi_wdata_24
    DIRECTION OUTPUT ;
    USE SIGNAL ;
    ANTENNAGATEAREA 0.434700 ;
    ANTENNADIFFAREA 1.137600 ;
    PORT
      LAYER met3 ;
        RECT 0.000 27.240 0.600 27.840 ;
    END
  END p3_axi_wdata_24
  PIN p3_axi_wdata_25
    DIRECTION OUTPUT ;
    USE SIGNAL ;
    ANTENNAGATEAREA 0.434700 ;
    ANTENNADIFFAREA 1.137600 ;
    PORT
      LAYER met2 ;
        RECT 51.610 170.550 51.890 170.830 ;
    END
  END p3_axi_wdata_25
  PIN p3_axi_wdata_26
    DIRECTION OUTPUT ;
    USE SIGNAL ;
    ANTENNAGATEAREA 0.434700 ;
    ANTENNADIFFAREA 1.137600 ;
    PORT
      LAYER met2 ;
        RECT 100.370 170.550 100.650 170.830 ;
    END
  END p3_axi_wdata_26
  PIN p3_axi_wdata_27
    DIRECTION OUTPUT ;
    USE SIGNAL ;
    ANTENNAGATEAREA 0.434700 ;
    ANTENNADIFFAREA 1.137600 ;
    PORT
      LAYER met3 ;
        RECT 159.510 107.480 160.110 108.080 ;
    END
  END p3_axi_wdata_27
  PIN p3_axi_wdata_28
    DIRECTION OUTPUT ;
    USE SIGNAL ;
    ANTENNAGATEAREA 0.434700 ;
    ANTENNADIFFAREA 1.137600 ;
    PORT
      LAYER met3 ;
        RECT 0.000 141.480 0.600 142.080 ;
    END
  END p3_axi_wdata_28
  PIN p3_axi_wdata_29
    DIRECTION OUTPUT ;
    USE SIGNAL ;
    ANTENNAGATEAREA 0.434700 ;
    ANTENNADIFFAREA 1.137600 ;
    PORT
      LAYER met2 ;
        RECT 87.490 170.550 87.770 170.830 ;
    END
  END p3_axi_wdata_29
  PIN p3_axi_wdata_3
    DIRECTION OUTPUT ;
    USE SIGNAL ;
    ANTENNAGATEAREA 0.434700 ;
    ANTENNADIFFAREA 1.137600 ;
    PORT
      LAYER met2 ;
        RECT 46.090 170.550 46.370 170.830 ;
    END
  END p3_axi_wdata_3
  PIN p3_axi_wdata_30
    DIRECTION OUTPUT ;
    USE SIGNAL ;
    ANTENNAGATEAREA 0.434700 ;
    ANTENNADIFFAREA 1.137600 ;
    PORT
      LAYER met3 ;
        RECT 0.000 95.240 0.600 95.840 ;
    END
  END p3_axi_wdata_30
  PIN p3_axi_wdata_31
    DIRECTION OUTPUT ;
    USE SIGNAL ;
    ANTENNAGATEAREA 0.434700 ;
    ANTENNADIFFAREA 1.137600 ;
    PORT
      LAYER met3 ;
        RECT 159.510 125.160 160.110 125.760 ;
    END
  END p3_axi_wdata_31
  PIN p3_axi_wdata_4
    DIRECTION OUTPUT ;
    USE SIGNAL ;
    ANTENNAGATEAREA 0.434700 ;
    ANTENNADIFFAREA 1.137600 ;
    PORT
      LAYER met3 ;
        RECT 0.000 136.040 0.600 136.640 ;
    END
  END p3_axi_wdata_4
  PIN p3_axi_wdata_5
    DIRECTION OUTPUT ;
    USE SIGNAL ;
    ANTENNAGATEAREA 0.434700 ;
    ANTENNADIFFAREA 1.137600 ;
    PORT
      LAYER met3 ;
        RECT 0.000 21.800 0.600 22.400 ;
    END
  END p3_axi_wdata_5
  PIN p3_axi_wdata_6
    DIRECTION OUTPUT ;
    USE SIGNAL ;
    ANTENNAGATEAREA 0.434700 ;
    ANTENNADIFFAREA 1.137600 ;
    PORT
      LAYER met2 ;
        RECT 70.930 170.550 71.210 170.830 ;
    END
  END p3_axi_wdata_6
  PIN p3_axi_wdata_7
    DIRECTION OUTPUT ;
    USE SIGNAL ;
    ANTENNAGATEAREA 0.434700 ;
    ANTENNADIFFAREA 1.137600 ;
    PORT
      LAYER met3 ;
        RECT 0.000 31.320 0.600 31.920 ;
    END
  END p3_axi_wdata_7
  PIN p3_axi_wdata_8
    DIRECTION OUTPUT ;
    USE SIGNAL ;
    ANTENNAGATEAREA 0.434700 ;
    ANTENNADIFFAREA 1.137600 ;
    PORT
      LAYER met3 ;
        RECT 0.000 16.360 0.600 16.960 ;
    END
  END p3_axi_wdata_8
  PIN p3_axi_wdata_9
    DIRECTION OUTPUT ;
    USE SIGNAL ;
    ANTENNAGATEAREA 0.434700 ;
    ANTENNADIFFAREA 1.137600 ;
    PORT
      LAYER met2 ;
        RECT 52.530 170.550 52.810 170.830 ;
    END
  END p3_axi_wdata_9
  PIN p3_axi_wready
    DIRECTION INPUT ;
    USE SIGNAL ;
    PORT
      LAYER met3 ;
        RECT 159.510 87.080 160.110 87.680 ;
    END
  END p3_axi_wready
  PIN p3_axi_wstrb_0
    DIRECTION OUTPUT ;
    USE SIGNAL ;
    ANTENNAGATEAREA 0.434700 ;
    ANTENNADIFFAREA 1.137600 ;
    PORT
      LAYER met2 ;
        RECT 116.930 170.550 117.210 170.830 ;
    END
  END p3_axi_wstrb_0
  PIN p3_axi_wstrb_1
    DIRECTION OUTPUT ;
    USE SIGNAL ;
    ANTENNAGATEAREA 0.434700 ;
    ANTENNADIFFAREA 1.137600 ;
    PORT
      LAYER met2 ;
        RECT 65.410 170.550 65.690 170.830 ;
    END
  END p3_axi_wstrb_1
  PIN p3_axi_wstrb_2
    DIRECTION OUTPUT ;
    USE SIGNAL ;
    ANTENNAGATEAREA 0.434700 ;
    ANTENNADIFFAREA 1.137600 ;
    PORT
      LAYER met3 ;
        RECT 0.000 28.600 0.600 29.200 ;
    END
  END p3_axi_wstrb_2
  PIN p3_axi_wstrb_3
    DIRECTION OUTPUT ;
    USE SIGNAL ;
    ANTENNAGATEAREA 0.434700 ;
    ANTENNADIFFAREA 1.137600 ;
    PORT
      LAYER met2 ;
        RECT 92.090 170.550 92.370 170.830 ;
    END
  END p3_axi_wstrb_3
  PIN p3_axi_wvalid
    DIRECTION OUTPUT ;
    USE SIGNAL ;
    ANTENNAGATEAREA 0.434700 ;
    ANTENNADIFFAREA 0.775300 ;
    PORT
      LAYER met3 ;
        RECT 0.000 145.560 0.600 146.160 ;
    END
  END p3_axi_wvalid
  PIN rst_n
    DIRECTION INPUT ;
    USE SIGNAL ;
    ANTENNAGATEAREA 0.647700 ;
    ANTENNADIFFAREA 0.434700 ;
    PORT
      LAYER met3 ;
        RECT 159.510 38.120 160.110 38.720 ;
    END
  END rst_n
  PIN s_axi_araddr_12
    DIRECTION INPUT ;
    USE SIGNAL ;
    PORT
      LAYER met3 ;
        RECT 159.510 62.600 160.110 63.200 ;
    END
  END s_axi_araddr_12
  PIN s_axi_araddr_13
    DIRECTION INPUT ;
    USE SIGNAL ;
    PORT
      LAYER met3 ;
        RECT 159.510 44.920 160.110 45.520 ;
    END
  END s_axi_araddr_13
  PIN s_axi_araddr_14
    DIRECTION INPUT ;
    USE SIGNAL ;
    PORT
      LAYER met3 ;
        RECT 159.510 46.280 160.110 46.880 ;
    END
  END s_axi_araddr_14
  PIN s_axi_araddr_15
    DIRECTION INPUT ;
    USE SIGNAL ;
    PORT
      LAYER met3 ;
        RECT 159.510 10.920 160.110 11.520 ;
    END
  END s_axi_araddr_15
  PIN s_axi_araddr_16
    DIRECTION INPUT ;
    USE SIGNAL ;
    PORT
      LAYER met3 ;
        RECT 159.510 49.000 160.110 49.600 ;
    END
  END s_axi_araddr_16
  PIN s_axi_araddr_17
    DIRECTION INPUT ;
    USE SIGNAL ;
    PORT
      LAYER met3 ;
        RECT 159.510 69.400 160.110 70.000 ;
    END
  END s_axi_araddr_17
  PIN s_axi_araddr_18
    DIRECTION INPUT ;
    USE SIGNAL ;
    PORT
      LAYER met3 ;
        RECT 159.510 51.720 160.110 52.320 ;
    END
  END s_axi_araddr_18
  PIN s_axi_araddr_19
    DIRECTION INPUT ;
    USE SIGNAL ;
    PORT
      LAYER met3 ;
        RECT 159.510 8.200 160.110 8.800 ;
    END
  END s_axi_araddr_19
  PIN s_axi_araddr_20
    DIRECTION INPUT ;
    USE SIGNAL ;
    PORT
      LAYER met3 ;
        RECT 159.510 146.920 160.110 147.520 ;
    END
  END s_axi_araddr_20
  PIN s_axi_araddr_21
    DIRECTION INPUT ;
    USE SIGNAL ;
    PORT
      LAYER met3 ;
        RECT 159.510 6.840 160.110 7.440 ;
    END
  END s_axi_araddr_21
  PIN s_axi_araddr_22
    DIRECTION INPUT ;
    USE SIGNAL ;
    PORT
      LAYER met3 ;
        RECT 159.510 57.160 160.110 57.760 ;
    END
  END s_axi_araddr_22
  PIN s_axi_araddr_23
    DIRECTION INPUT ;
    USE SIGNAL ;
    PORT
      LAYER met3 ;
        RECT 159.510 63.960 160.110 64.560 ;
    END
  END s_axi_araddr_23
  PIN s_axi_araddr_24
    DIRECTION INPUT ;
    USE SIGNAL ;
    PORT
      LAYER met3 ;
        RECT 159.510 59.880 160.110 60.480 ;
    END
  END s_axi_araddr_24
  PIN s_axi_araddr_25
    DIRECTION INPUT ;
    USE SIGNAL ;
    PORT
      LAYER met3 ;
        RECT 159.510 61.240 160.110 61.840 ;
    END
  END s_axi_araddr_25
  PIN s_axi_araddr_26
    DIRECTION INPUT ;
    USE SIGNAL ;
    PORT
      LAYER met3 ;
        RECT 159.510 12.280 160.110 12.880 ;
    END
  END s_axi_araddr_26
  PIN s_axi_araddr_27
    DIRECTION INPUT ;
    USE SIGNAL ;
    PORT
      LAYER met3 ;
        RECT 159.510 153.720 160.110 154.320 ;
    END
  END s_axi_araddr_27
  PIN s_axi_araddr_28
    DIRECTION INPUT ;
    USE SIGNAL ;
    PORT
      LAYER met3 ;
        RECT 159.510 65.320 160.110 65.920 ;
    END
  END s_axi_araddr_28
  PIN s_axi_araddr_29
    DIRECTION INPUT ;
    USE SIGNAL ;
    PORT
      LAYER met3 ;
        RECT 159.510 5.480 160.110 6.080 ;
    END
  END s_axi_araddr_29
  PIN s_axi_araddr_30
    DIRECTION INPUT ;
    USE SIGNAL ;
    PORT
      LAYER met3 ;
        RECT 159.510 163.240 160.110 163.840 ;
    END
  END s_axi_araddr_30
  PIN s_axi_araddr_31
    DIRECTION INPUT ;
    USE SIGNAL ;
    PORT
      LAYER met3 ;
        RECT 159.510 168.680 160.110 169.280 ;
    END
  END s_axi_araddr_31
  PIN s_axi_arready
    DIRECTION OUTPUT ;
    USE SIGNAL ;
    ANTENNAGATEAREA 0.434700 ;
    ANTENNADIFFAREA 1.137600 ;
    PORT
      LAYER met3 ;
        RECT 159.510 53.080 160.110 53.680 ;
    END
  END s_axi_arready
  PIN s_axi_awaddr_12
    DIRECTION INPUT ;
    USE SIGNAL ;
    PORT
      LAYER met3 ;
        RECT 159.510 70.760 160.110 71.360 ;
    END
  END s_axi_awaddr_12
  PIN s_axi_awaddr_13
    DIRECTION INPUT ;
    USE SIGNAL ;
    PORT
      LAYER met3 ;
        RECT 159.510 13.640 160.110 14.240 ;
    END
  END s_axi_awaddr_13
  PIN s_axi_awaddr_14
    DIRECTION INPUT ;
    USE SIGNAL ;
    PORT
      LAYER met3 ;
        RECT 159.510 88.440 160.110 89.040 ;
    END
  END s_axi_awaddr_14
  PIN s_axi_awaddr_15
    DIRECTION INPUT ;
    USE SIGNAL ;
    PORT
      LAYER met3 ;
        RECT 159.510 157.800 160.110 158.400 ;
    END
  END s_axi_awaddr_15
  PIN s_axi_awaddr_16
    DIRECTION INPUT ;
    USE SIGNAL ;
    PORT
      LAYER met3 ;
        RECT 159.510 167.320 160.110 167.920 ;
    END
  END s_axi_awaddr_16
  PIN s_axi_awaddr_17
    DIRECTION INPUT ;
    USE SIGNAL ;
    PORT
      LAYER met3 ;
        RECT 159.510 77.560 160.110 78.160 ;
    END
  END s_axi_awaddr_17
  PIN s_axi_awaddr_18
    DIRECTION INPUT ;
    USE SIGNAL ;
    PORT
      LAYER met3 ;
        RECT 159.510 140.120 160.110 140.720 ;
    END
  END s_axi_awaddr_18
  PIN s_axi_awaddr_19
    DIRECTION INPUT ;
    USE SIGNAL ;
    PORT
      LAYER met3 ;
        RECT 159.510 85.720 160.110 86.320 ;
    END
  END s_axi_awaddr_19
  PIN s_axi_awaddr_20
    DIRECTION INPUT ;
    USE SIGNAL ;
    PORT
      LAYER met3 ;
        RECT 159.510 134.680 160.110 135.280 ;
    END
  END s_axi_awaddr_20
  PIN s_axi_awaddr_21
    DIRECTION INPUT ;
    USE SIGNAL ;
    PORT
      LAYER met3 ;
        RECT 159.510 144.200 160.110 144.800 ;
    END
  END s_axi_awaddr_21
  PIN s_axi_awaddr_22
    DIRECTION INPUT ;
    USE SIGNAL ;
    PORT
      LAYER met3 ;
        RECT 159.510 84.360 160.110 84.960 ;
    END
  END s_axi_awaddr_22
  PIN s_axi_awaddr_23
    DIRECTION INPUT ;
    USE SIGNAL ;
    PORT
      LAYER met3 ;
        RECT 159.510 24.520 160.110 25.120 ;
    END
  END s_axi_awaddr_23
  PIN s_axi_awaddr_24
    DIRECTION INPUT ;
    USE SIGNAL ;
    PORT
      LAYER met3 ;
        RECT 159.510 159.160 160.110 159.760 ;
    END
  END s_axi_awaddr_24
  PIN s_axi_awaddr_25
    DIRECTION INPUT ;
    USE SIGNAL ;
    PORT
      LAYER met3 ;
        RECT 159.510 2.760 160.110 3.360 ;
    END
  END s_axi_awaddr_25
  PIN s_axi_awaddr_26
    DIRECTION INPUT ;
    USE SIGNAL ;
    PORT
      LAYER met3 ;
        RECT 159.510 89.800 160.110 90.400 ;
    END
  END s_axi_awaddr_26
  PIN s_axi_awaddr_27
    DIRECTION INPUT ;
    USE SIGNAL ;
    PORT
      LAYER met3 ;
        RECT 159.510 164.600 160.110 165.200 ;
    END
  END s_axi_awaddr_27
  PIN s_axi_awaddr_28
    DIRECTION INPUT ;
    USE SIGNAL ;
    PORT
      LAYER met3 ;
        RECT 159.510 4.120 160.110 4.720 ;
    END
  END s_axi_awaddr_28
  PIN s_axi_awaddr_29
    DIRECTION INPUT ;
    USE SIGNAL ;
    PORT
      LAYER met3 ;
        RECT 159.510 9.560 160.110 10.160 ;
    END
  END s_axi_awaddr_29
  PIN s_axi_awaddr_30
    DIRECTION INPUT ;
    USE SIGNAL ;
    PORT
      LAYER met3 ;
        RECT 159.510 17.720 160.110 18.320 ;
    END
  END s_axi_awaddr_30
  PIN s_axi_awaddr_31
    DIRECTION INPUT ;
    USE SIGNAL ;
    PORT
      LAYER met3 ;
        RECT 159.510 19.080 160.110 19.680 ;
    END
  END s_axi_awaddr_31
  PIN s_axi_awready
    DIRECTION OUTPUT ;
    USE SIGNAL ;
    ANTENNAGATEAREA 0.434700 ;
    ANTENNADIFFAREA 1.137600 ;
    PORT
      LAYER met3 ;
        RECT 159.510 73.480 160.110 74.080 ;
    END
  END s_axi_awready
  PIN s_axi_bresp_0
    DIRECTION OUTPUT ;
    USE SIGNAL ;
    ANTENNAGATEAREA 0.434700 ;
    ANTENNADIFFAREA 0.775300 ;
    PORT
      LAYER met3 ;
        RECT 0.000 39.480 0.600 40.080 ;
    END
  END s_axi_bresp_0
  PIN s_axi_bresp_1
    DIRECTION OUTPUT ;
    USE SIGNAL ;
    ANTENNAGATEAREA 0.434700 ;
    ANTENNADIFFAREA 0.775300 ;
    PORT
      LAYER met3 ;
        RECT 0.000 57.160 0.600 57.760 ;
    END
  END s_axi_bresp_1
  PIN s_axi_bvalid
    DIRECTION OUTPUT ;
    USE SIGNAL ;
    ANTENNAGATEAREA 0.434700 ;
    ANTENNADIFFAREA 0.775300 ;
    PORT
      LAYER met3 ;
        RECT 0.000 85.720 0.600 86.320 ;
    END
  END s_axi_bvalid
  PIN s_axi_rdata_0
    DIRECTION OUTPUT ;
    USE SIGNAL ;
    PORT
      LAYER met3 ;
        RECT 159.510 54.440 160.110 55.040 ;
    END
  END s_axi_rdata_0
  PIN s_axi_rdata_1
    DIRECTION OUTPUT ;
    USE SIGNAL ;
    PORT
      LAYER met3 ;
        RECT 159.510 149.640 160.110 150.240 ;
    END
  END s_axi_rdata_1
  PIN s_axi_rdata_10
    DIRECTION OUTPUT ;
    USE SIGNAL ;
    PORT
      LAYER met3 ;
        RECT 159.510 148.280 160.110 148.880 ;
    END
  END s_axi_rdata_10
  PIN s_axi_rdata_11
    DIRECTION OUTPUT ;
    USE SIGNAL ;
    PORT
      LAYER met3 ;
        RECT 159.510 25.880 160.110 26.480 ;
    END
  END s_axi_rdata_11
  PIN s_axi_rdata_12
    DIRECTION OUTPUT ;
    USE SIGNAL ;
    PORT
      LAYER met3 ;
        RECT 159.510 137.400 160.110 138.000 ;
    END
  END s_axi_rdata_12
  PIN s_axi_rdata_13
    DIRECTION OUTPUT ;
    USE SIGNAL ;
    PORT
      LAYER met3 ;
        RECT 159.510 138.760 160.110 139.360 ;
    END
  END s_axi_rdata_13
  PIN s_axi_rdata_14
    DIRECTION OUTPUT ;
    USE SIGNAL ;
    ANTENNAGATEAREA 0.434700 ;
    ANTENNADIFFAREA 0.775300 ;
    PORT
      LAYER met3 ;
        RECT 0.000 62.600 0.600 63.200 ;
    END
  END s_axi_rdata_14
  PIN s_axi_rdata_15
    DIRECTION OUTPUT ;
    USE SIGNAL ;
    PORT
      LAYER met3 ;
        RECT 159.510 161.880 160.110 162.480 ;
    END
  END s_axi_rdata_15
  PIN s_axi_rdata_16
    DIRECTION OUTPUT ;
    USE SIGNAL ;
    PORT
      LAYER met3 ;
        RECT 159.510 47.640 160.110 48.240 ;
    END
  END s_axi_rdata_16
  PIN s_axi_rdata_17
    DIRECTION OUTPUT ;
    USE SIGNAL ;
    ANTENNAGATEAREA 0.434700 ;
    ANTENNADIFFAREA 0.775300 ;
    PORT
      LAYER met3 ;
        RECT 0.000 68.040 0.600 68.640 ;
    END
  END s_axi_rdata_17
  PIN s_axi_rdata_18
    DIRECTION OUTPUT ;
    USE SIGNAL ;
    PORT
      LAYER met3 ;
        RECT 159.510 152.360 160.110 152.960 ;
    END
  END s_axi_rdata_18
  PIN s_axi_rdata_19
    DIRECTION OUTPUT ;
    USE SIGNAL ;
    PORT
      LAYER met3 ;
        RECT 159.510 31.320 160.110 31.920 ;
    END
  END s_axi_rdata_19
  PIN s_axi_rdata_2
    DIRECTION OUTPUT ;
    USE SIGNAL ;
    PORT
      LAYER met3 ;
        RECT 159.510 160.520 160.110 161.120 ;
    END
  END s_axi_rdata_2
  PIN s_axi_rdata_20
    DIRECTION OUTPUT ;
    USE SIGNAL ;
    ANTENNAGATEAREA 0.434700 ;
    ANTENNADIFFAREA 0.775300 ;
    PORT
      LAYER met3 ;
        RECT 0.000 49.000 0.600 49.600 ;
    END
  END s_axi_rdata_20
  PIN s_axi_rdata_21
    DIRECTION OUTPUT ;
    USE SIGNAL ;
    PORT
      LAYER met3 ;
        RECT 159.510 136.040 160.110 136.640 ;
    END
  END s_axi_rdata_21
  PIN s_axi_rdata_22
    DIRECTION OUTPUT ;
    USE SIGNAL ;
    ANTENNAGATEAREA 0.434700 ;
    ANTENNADIFFAREA 0.775300 ;
    PORT
      LAYER met3 ;
        RECT 0.000 58.520 0.600 59.120 ;
    END
  END s_axi_rdata_22
  PIN s_axi_rdata_23
    DIRECTION OUTPUT ;
    USE SIGNAL ;
    PORT
      LAYER met3 ;
        RECT 159.510 142.840 160.110 143.440 ;
    END
  END s_axi_rdata_23
  PIN s_axi_rdata_24
    DIRECTION OUTPUT ;
    USE SIGNAL ;
    ANTENNAGATEAREA 0.434700 ;
    ANTENNADIFFAREA 0.775300 ;
    PORT
      LAYER met3 ;
        RECT 0.000 40.840 0.600 41.440 ;
    END
  END s_axi_rdata_24
  PIN s_axi_rdata_25
    DIRECTION OUTPUT ;
    USE SIGNAL ;
    PORT
      LAYER met3 ;
        RECT 159.510 27.240 160.110 27.840 ;
    END
  END s_axi_rdata_25
  PIN s_axi_rdata_26
    DIRECTION OUTPUT ;
    USE SIGNAL ;
    PORT
      LAYER met3 ;
        RECT 159.510 133.320 160.110 133.920 ;
    END
  END s_axi_rdata_26
  PIN s_axi_rdata_27
    DIRECTION OUTPUT ;
    USE SIGNAL ;
    PORT
      LAYER met3 ;
        RECT 159.510 131.960 160.110 132.560 ;
    END
  END s_axi_rdata_27
  PIN s_axi_rdata_28
    DIRECTION OUTPUT ;
    USE SIGNAL ;
    PORT
      LAYER met3 ;
        RECT 159.510 130.600 160.110 131.200 ;
    END
  END s_axi_rdata_28
  PIN s_axi_rdata_29
    DIRECTION OUTPUT ;
    USE SIGNAL ;
    ANTENNAGATEAREA 0.434700 ;
    ANTENNADIFFAREA 0.775300 ;
    PORT
      LAYER met3 ;
        RECT 0.000 153.720 0.600 154.320 ;
    END
  END s_axi_rdata_29
  PIN s_axi_rdata_3
    DIRECTION OUTPUT ;
    USE SIGNAL ;
    PORT
      LAYER met3 ;
        RECT 159.510 156.440 160.110 157.040 ;
    END
  END s_axi_rdata_3
  PIN s_axi_rdata_30
    DIRECTION OUTPUT ;
    USE SIGNAL ;
    PORT
      LAYER met3 ;
        RECT 159.510 40.840 160.110 41.440 ;
    END
  END s_axi_rdata_30
  PIN s_axi_rdata_31
    DIRECTION OUTPUT ;
    USE SIGNAL ;
    PORT
      LAYER met3 ;
        RECT 159.510 21.800 160.110 22.400 ;
    END
  END s_axi_rdata_31
  PIN s_axi_rdata_4
    DIRECTION OUTPUT ;
    USE SIGNAL ;
    ANTENNAGATEAREA 0.434700 ;
    ANTENNADIFFAREA 0.775300 ;
    PORT
      LAYER met3 ;
        RECT 0.000 38.120 0.600 38.720 ;
    END
  END s_axi_rdata_4
  PIN s_axi_rdata_5
    DIRECTION OUTPUT ;
    USE SIGNAL ;
    PORT
      LAYER met3 ;
        RECT 159.510 1.400 160.110 2.000 ;
    END
  END s_axi_rdata_5
  PIN s_axi_rdata_6
    DIRECTION OUTPUT ;
    USE SIGNAL ;
    PORT
      LAYER met2 ;
        RECT 157.410 170.550 157.690 170.830 ;
    END
  END s_axi_rdata_6
  PIN s_axi_rdata_7
    DIRECTION OUTPUT ;
    USE SIGNAL ;
    PORT
      LAYER met2 ;
        RECT 156.490 170.550 156.770 170.830 ;
    END
  END s_axi_rdata_7
  PIN s_axi_rdata_8
    DIRECTION OUTPUT ;
    USE SIGNAL ;
    ANTENNAGATEAREA 0.434700 ;
    ANTENNADIFFAREA 0.775300 ;
    PORT
      LAYER met3 ;
        RECT 0.000 50.360 0.600 50.960 ;
    END
  END s_axi_rdata_8
  PIN s_axi_rdata_9
    DIRECTION OUTPUT ;
    USE SIGNAL ;
    PORT
      LAYER met2 ;
        RECT 155.570 170.550 155.850 170.830 ;
    END
  END s_axi_rdata_9
  PIN s_axi_rready
    DIRECTION INPUT ;
    USE SIGNAL ;
    PORT
      LAYER met2 ;
        RECT 154.650 170.550 154.930 170.830 ;
    END
  END s_axi_rready
  PIN s_axi_rresp_0
    DIRECTION OUTPUT ;
    USE SIGNAL ;
    PORT
      LAYER met2 ;
        RECT 153.730 170.550 154.010 170.830 ;
    END
  END s_axi_rresp_0
  PIN s_axi_rresp_1
    DIRECTION OUTPUT ;
    USE SIGNAL ;
    PORT
      LAYER met2 ;
        RECT 152.810 170.550 153.090 170.830 ;
    END
  END s_axi_rresp_1
  PIN s_axi_rvalid
    DIRECTION OUTPUT ;
    USE SIGNAL ;
    PORT
      LAYER met2 ;
        RECT 151.890 170.550 152.170 170.830 ;
    END
  END s_axi_rvalid
  PIN s_axi_wready
    DIRECTION OUTPUT ;
    USE SIGNAL ;
    ANTENNAGATEAREA 0.434700 ;
    ANTENNADIFFAREA 0.434700 ;
    PORT
      LAYER met3 ;
        RECT 0.000 42.200 0.600 42.800 ;
    END
  END s_axi_wready
  PIN s_axi_wvalid
    DIRECTION INPUT ;
    USE SIGNAL ;
    PORT
      LAYER met2 ;
        RECT 150.970 170.550 151.250 170.830 ;
    END
  END s_axi_wvalid
  OBS
      LAYER nwell ;
        RECT 5.330 10.795 154.750 157.845 ;
      LAYER li1 ;
        RECT 5.520 10.795 154.560 157.845 ;
      LAYER met1 ;
        RECT 5.130 10.240 154.560 159.760 ;
      LAYER met2 ;
        RECT 5.150 170.270 34.770 170.550 ;
        RECT 35.610 170.270 35.690 170.550 ;
        RECT 36.530 170.270 36.610 170.550 ;
        RECT 37.450 170.270 37.530 170.550 ;
        RECT 38.370 170.270 40.290 170.550 ;
        RECT 41.130 170.270 41.210 170.550 ;
        RECT 42.050 170.270 42.130 170.550 ;
        RECT 42.970 170.270 43.050 170.550 ;
        RECT 43.890 170.270 44.890 170.550 ;
        RECT 45.730 170.270 45.810 170.550 ;
        RECT 46.650 170.270 46.730 170.550 ;
        RECT 47.570 170.270 47.650 170.550 ;
        RECT 48.490 170.270 48.570 170.550 ;
        RECT 49.410 170.270 49.490 170.550 ;
        RECT 50.330 170.270 50.410 170.550 ;
        RECT 51.250 170.270 51.330 170.550 ;
        RECT 52.170 170.270 52.250 170.550 ;
        RECT 53.090 170.270 53.170 170.550 ;
        RECT 54.010 170.270 54.090 170.550 ;
        RECT 54.930 170.270 55.010 170.550 ;
        RECT 55.850 170.270 55.930 170.550 ;
        RECT 56.770 170.270 56.850 170.550 ;
        RECT 57.690 170.270 57.770 170.550 ;
        RECT 58.610 170.270 58.690 170.550 ;
        RECT 59.530 170.270 59.610 170.550 ;
        RECT 60.450 170.270 60.530 170.550 ;
        RECT 61.370 170.270 61.450 170.550 ;
        RECT 62.290 170.270 62.370 170.550 ;
        RECT 63.210 170.270 63.290 170.550 ;
        RECT 64.130 170.270 64.210 170.550 ;
        RECT 65.050 170.270 65.130 170.550 ;
        RECT 65.970 170.270 66.050 170.550 ;
        RECT 66.890 170.270 66.970 170.550 ;
        RECT 67.810 170.270 67.890 170.550 ;
        RECT 68.730 170.270 68.810 170.550 ;
        RECT 69.650 170.270 69.730 170.550 ;
        RECT 70.570 170.270 70.650 170.550 ;
        RECT 71.490 170.270 71.570 170.550 ;
        RECT 72.410 170.270 72.490 170.550 ;
        RECT 73.330 170.270 73.410 170.550 ;
        RECT 74.250 170.270 74.330 170.550 ;
        RECT 75.170 170.270 75.250 170.550 ;
        RECT 76.090 170.270 76.170 170.550 ;
        RECT 77.010 170.270 77.090 170.550 ;
        RECT 77.930 170.270 78.010 170.550 ;
        RECT 78.850 170.270 78.930 170.550 ;
        RECT 79.770 170.270 79.850 170.550 ;
        RECT 80.690 170.270 80.770 170.550 ;
        RECT 81.610 170.270 81.690 170.550 ;
        RECT 82.530 170.270 82.610 170.550 ;
        RECT 83.450 170.270 83.530 170.550 ;
        RECT 84.370 170.270 84.450 170.550 ;
        RECT 85.290 170.270 85.370 170.550 ;
        RECT 86.210 170.270 86.290 170.550 ;
        RECT 87.130 170.270 87.210 170.550 ;
        RECT 88.050 170.270 88.130 170.550 ;
        RECT 88.970 170.270 89.050 170.550 ;
        RECT 89.890 170.270 89.970 170.550 ;
        RECT 90.810 170.270 90.890 170.550 ;
        RECT 91.730 170.270 91.810 170.550 ;
        RECT 92.650 170.270 92.730 170.550 ;
        RECT 93.570 170.270 93.650 170.550 ;
        RECT 94.490 170.270 94.570 170.550 ;
        RECT 95.410 170.270 95.490 170.550 ;
        RECT 96.330 170.270 96.410 170.550 ;
        RECT 97.250 170.270 97.330 170.550 ;
        RECT 98.170 170.270 98.250 170.550 ;
        RECT 99.090 170.270 99.170 170.550 ;
        RECT 100.010 170.270 100.090 170.550 ;
        RECT 100.930 170.270 101.010 170.550 ;
        RECT 101.850 170.270 101.930 170.550 ;
        RECT 102.770 170.270 102.850 170.550 ;
        RECT 103.690 170.270 103.770 170.550 ;
        RECT 104.610 170.270 104.690 170.550 ;
        RECT 105.530 170.270 105.610 170.550 ;
        RECT 106.450 170.270 110.210 170.550 ;
        RECT 111.050 170.270 111.130 170.550 ;
        RECT 111.970 170.270 112.050 170.550 ;
        RECT 112.890 170.270 112.970 170.550 ;
        RECT 113.810 170.270 113.890 170.550 ;
        RECT 114.730 170.270 114.810 170.550 ;
        RECT 115.650 170.270 115.730 170.550 ;
        RECT 116.570 170.270 116.650 170.550 ;
        RECT 117.490 170.270 123.090 170.550 ;
        RECT 123.930 170.270 124.010 170.550 ;
        RECT 124.850 170.270 124.930 170.550 ;
        RECT 125.770 170.270 125.850 170.550 ;
        RECT 126.690 170.270 126.770 170.550 ;
        RECT 127.610 170.270 127.690 170.550 ;
        RECT 128.530 170.270 128.610 170.550 ;
        RECT 129.450 170.270 129.530 170.550 ;
        RECT 130.370 170.270 150.690 170.550 ;
        RECT 151.530 170.270 151.610 170.550 ;
        RECT 152.450 170.270 152.530 170.550 ;
        RECT 153.370 170.270 153.450 170.550 ;
        RECT 154.290 170.270 154.370 170.550 ;
        RECT 5.150 0.560 154.470 170.270 ;
        RECT 5.250 0.280 5.330 0.560 ;
        RECT 6.170 0.280 6.250 0.560 ;
        RECT 7.090 0.280 7.170 0.560 ;
        RECT 8.010 0.280 8.090 0.560 ;
        RECT 8.930 0.280 9.010 0.560 ;
        RECT 9.850 0.280 9.930 0.560 ;
        RECT 10.770 0.280 10.850 0.560 ;
        RECT 11.690 0.280 11.770 0.560 ;
        RECT 12.610 0.280 12.690 0.560 ;
        RECT 13.530 0.280 13.610 0.560 ;
        RECT 14.450 0.280 14.530 0.560 ;
        RECT 15.370 0.280 15.450 0.560 ;
        RECT 16.290 0.280 16.370 0.560 ;
        RECT 17.210 0.280 17.290 0.560 ;
        RECT 18.130 0.280 18.210 0.560 ;
        RECT 19.050 0.280 19.130 0.560 ;
        RECT 19.970 0.280 20.050 0.560 ;
        RECT 20.890 0.280 20.970 0.560 ;
        RECT 21.810 0.280 21.890 0.560 ;
        RECT 22.730 0.280 22.810 0.560 ;
        RECT 23.650 0.280 23.730 0.560 ;
        RECT 24.570 0.280 24.650 0.560 ;
        RECT 25.490 0.280 25.570 0.560 ;
        RECT 26.410 0.280 26.490 0.560 ;
        RECT 27.330 0.280 27.410 0.560 ;
        RECT 28.250 0.280 28.330 0.560 ;
        RECT 29.170 0.280 29.250 0.560 ;
        RECT 30.090 0.280 30.170 0.560 ;
        RECT 31.010 0.280 31.090 0.560 ;
        RECT 31.930 0.280 32.010 0.560 ;
        RECT 32.850 0.280 32.930 0.560 ;
        RECT 33.770 0.280 33.850 0.560 ;
        RECT 34.690 0.280 34.770 0.560 ;
        RECT 35.610 0.280 35.690 0.560 ;
        RECT 36.530 0.280 36.610 0.560 ;
        RECT 37.450 0.280 37.530 0.560 ;
        RECT 38.370 0.280 38.450 0.560 ;
        RECT 39.290 0.280 39.370 0.560 ;
        RECT 40.210 0.280 40.290 0.560 ;
        RECT 41.130 0.280 41.210 0.560 ;
        RECT 42.050 0.280 42.130 0.560 ;
        RECT 42.970 0.280 43.050 0.560 ;
        RECT 43.890 0.280 43.970 0.560 ;
        RECT 44.810 0.280 44.890 0.560 ;
        RECT 45.730 0.280 45.810 0.560 ;
        RECT 46.650 0.280 46.730 0.560 ;
        RECT 47.570 0.280 47.650 0.560 ;
        RECT 48.490 0.280 48.570 0.560 ;
        RECT 49.410 0.280 49.490 0.560 ;
        RECT 50.330 0.280 50.410 0.560 ;
        RECT 51.250 0.280 51.330 0.560 ;
        RECT 52.170 0.280 52.250 0.560 ;
        RECT 53.090 0.280 53.170 0.560 ;
        RECT 54.010 0.280 54.090 0.560 ;
        RECT 54.930 0.280 55.010 0.560 ;
        RECT 55.850 0.280 55.930 0.560 ;
        RECT 56.770 0.280 56.850 0.560 ;
        RECT 57.690 0.280 57.770 0.560 ;
        RECT 58.610 0.280 58.690 0.560 ;
        RECT 59.530 0.280 59.610 0.560 ;
        RECT 60.450 0.280 60.530 0.560 ;
        RECT 61.370 0.280 61.450 0.560 ;
        RECT 62.290 0.280 62.370 0.560 ;
        RECT 63.210 0.280 63.290 0.560 ;
        RECT 64.130 0.280 64.210 0.560 ;
        RECT 65.050 0.280 65.130 0.560 ;
        RECT 65.970 0.280 66.050 0.560 ;
        RECT 66.890 0.280 66.970 0.560 ;
        RECT 67.810 0.280 67.890 0.560 ;
        RECT 68.730 0.280 68.810 0.560 ;
        RECT 69.650 0.280 69.730 0.560 ;
        RECT 70.570 0.280 70.650 0.560 ;
        RECT 71.490 0.280 71.570 0.560 ;
        RECT 72.410 0.280 72.490 0.560 ;
        RECT 73.330 0.280 73.410 0.560 ;
        RECT 74.250 0.280 74.330 0.560 ;
        RECT 75.170 0.280 75.250 0.560 ;
        RECT 76.090 0.280 76.170 0.560 ;
        RECT 77.010 0.280 77.090 0.560 ;
        RECT 77.930 0.280 78.010 0.560 ;
        RECT 78.850 0.280 78.930 0.560 ;
        RECT 79.770 0.280 79.850 0.560 ;
        RECT 80.690 0.280 80.770 0.560 ;
        RECT 81.610 0.280 81.690 0.560 ;
        RECT 82.530 0.280 82.610 0.560 ;
        RECT 83.450 0.280 83.530 0.560 ;
        RECT 84.370 0.280 84.450 0.560 ;
        RECT 85.290 0.280 85.370 0.560 ;
        RECT 86.210 0.280 86.290 0.560 ;
        RECT 87.130 0.280 87.210 0.560 ;
        RECT 88.050 0.280 88.130 0.560 ;
        RECT 88.970 0.280 89.050 0.560 ;
        RECT 89.890 0.280 89.970 0.560 ;
        RECT 90.810 0.280 90.890 0.560 ;
        RECT 91.730 0.280 91.810 0.560 ;
        RECT 92.650 0.280 92.730 0.560 ;
        RECT 93.570 0.280 93.650 0.560 ;
        RECT 94.490 0.280 94.570 0.560 ;
        RECT 95.410 0.280 95.490 0.560 ;
        RECT 96.330 0.280 96.410 0.560 ;
        RECT 97.250 0.280 97.330 0.560 ;
        RECT 98.170 0.280 98.250 0.560 ;
        RECT 99.090 0.280 99.170 0.560 ;
        RECT 100.010 0.280 100.090 0.560 ;
        RECT 100.930 0.280 101.010 0.560 ;
        RECT 101.850 0.280 101.930 0.560 ;
        RECT 102.770 0.280 102.850 0.560 ;
        RECT 103.690 0.280 103.770 0.560 ;
        RECT 104.610 0.280 104.690 0.560 ;
        RECT 105.530 0.280 105.610 0.560 ;
        RECT 106.450 0.280 106.530 0.560 ;
        RECT 107.370 0.280 107.450 0.560 ;
        RECT 108.290 0.280 108.370 0.560 ;
        RECT 109.210 0.280 109.290 0.560 ;
        RECT 110.130 0.280 110.210 0.560 ;
        RECT 111.050 0.280 111.130 0.560 ;
        RECT 111.970 0.280 112.050 0.560 ;
        RECT 112.890 0.280 112.970 0.560 ;
        RECT 113.810 0.280 113.890 0.560 ;
        RECT 114.730 0.280 114.810 0.560 ;
        RECT 115.650 0.280 115.730 0.560 ;
        RECT 116.570 0.280 116.650 0.560 ;
        RECT 117.490 0.280 117.570 0.560 ;
        RECT 118.410 0.280 118.490 0.560 ;
        RECT 119.330 0.280 119.410 0.560 ;
        RECT 120.250 0.280 120.330 0.560 ;
        RECT 121.170 0.280 121.250 0.560 ;
        RECT 122.090 0.280 122.170 0.560 ;
        RECT 123.010 0.280 123.090 0.560 ;
        RECT 123.930 0.280 124.010 0.560 ;
        RECT 124.850 0.280 124.930 0.560 ;
        RECT 125.770 0.280 125.850 0.560 ;
        RECT 126.690 0.280 126.770 0.560 ;
        RECT 127.610 0.280 127.690 0.560 ;
        RECT 128.530 0.280 128.610 0.560 ;
        RECT 129.450 0.280 129.530 0.560 ;
        RECT 130.370 0.280 130.450 0.560 ;
        RECT 131.290 0.280 131.370 0.560 ;
        RECT 132.210 0.280 132.290 0.560 ;
        RECT 133.130 0.280 133.210 0.560 ;
        RECT 134.050 0.280 134.130 0.560 ;
        RECT 134.970 0.280 135.050 0.560 ;
        RECT 135.890 0.280 135.970 0.560 ;
        RECT 136.810 0.280 136.890 0.560 ;
        RECT 137.730 0.280 137.810 0.560 ;
        RECT 138.650 0.280 138.730 0.560 ;
        RECT 139.570 0.280 139.650 0.560 ;
        RECT 140.490 0.280 140.570 0.560 ;
        RECT 141.410 0.280 141.490 0.560 ;
        RECT 142.330 0.280 142.410 0.560 ;
        RECT 143.250 0.280 143.330 0.560 ;
        RECT 144.170 0.280 144.250 0.560 ;
        RECT 145.090 0.280 145.170 0.560 ;
        RECT 146.010 0.280 146.090 0.560 ;
        RECT 146.930 0.280 147.010 0.560 ;
        RECT 147.850 0.280 147.930 0.560 ;
        RECT 148.770 0.280 148.850 0.560 ;
        RECT 149.690 0.280 149.770 0.560 ;
        RECT 150.610 0.280 150.690 0.560 ;
        RECT 151.530 0.280 151.610 0.560 ;
        RECT 152.450 0.280 152.530 0.560 ;
        RECT 153.370 0.280 153.450 0.560 ;
        RECT 154.290 0.280 154.370 0.560 ;
      LAYER met3 ;
        RECT 1.000 1.535 159.110 158.265 ;
      LAYER met4 ;
        RECT 42.615 130.055 75.145 152.145 ;
  END
END security_axi_mux
END LIBRARY

